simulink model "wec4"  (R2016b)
settings: Solver=ode4  StartTime=0  StopTime=1000  FixedStep=0.005  MaxStep=0.005  RelTol=1e-3  EnableMultiTasking=on
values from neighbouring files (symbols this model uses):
  arAdaptiveLawData = 1/2*zModelSimple.zModelPto.arFreq.*     zModelSimple.zModelPto.arMagnitude./     cos(zModelSimple.zModelPto.arPhase*pi/180+pi/2)    [IMPACT_Control.m]
  arAdaptiveLawDataX = 1/2*zModelSimpleX.zModelPto.arFreq.*         zModelSimpleX.zModelPto.arMagnitude./         cos(zModelSimpleX.zModelPto.arPhase*pi/180+pi/2)    [IMPACT_Control.m]
  arControllerRampGain = [0,0,1,1]    [IMPACT_Control.m]
  arControllerRampTime = [0 rStartRampTime rStartRampTime+rRampTimeLength 8000]    [IMPACT_Control.m]
  arEkfInitialisation = zeros(1,11)    [IMPACT_Control.m]
  arEkfInitialisationX = zeros(1,11)    [IMPACT_Control.m]
  arFrequency = zModelSimple.zModelPto.arFreq    [IMPACT_Control.m]
  arFrequencyRange = zModelSimple.zModelPto.arFreq    [IMPACT_Control.m]
  arFrequencyX = zModelSimpleX.zModelPto.arFreq    [IMPACT_Control.m]
  arImpedance = 1./zModelSimple.zModelPto.arMagnitude./zModelSimple.zModelPto.arFreq    [IMPACT_Control.m]
  arImpedanceX = 1./zModelSimpleX.zModelPto.arMagnitude./zModelSimpleX.zModelPto.arFreq    [IMPACT_Control.m]
  CentralPTOPreload = -1.6113e+07    (= -16113000)    [wecSimInputFile.m]
  F1 = [4.243 2.375 -12.243]    [wecSimInputFile.m]
  F2 = [4.243 -2.375 -12.243]    [wecSimInputFile.m]
  F3 = [-4.243 -2.375 -12.243]    [wecSimInputFile.m]
  F4 = [-4.243 2.375 -12.243]    [wecSimInputFile.m]
  FC = [0 0 -14]    [wecSimInputFile.m]
  iAdaptiveDamping = 0    [wec4IMPACT_Project.m]    (also in IMPACT_Control.m = handles.iAdaptiveDamping; wec1_IMPACT_Project.m; wec2_IMPACT_Project.m; wec3_IMPACT_Project.m)
  iControlType = 2    [wec4IMPACT_Project.m]    (also in IMPACT_Control.m = handles.iControlType; wec1_IMPACT_Project.m = 1; wec2_IMPACT_Project.m = 1; wec3_IMPACT_Project.m = 1)
  iPtoPositionConstraint = 1    [wec4IMPACT_Project.m]    (also in IMPACT_Control.m = handles.iPtoPositionConstraint; wec1_IMPACT_Project.m = 0; wec2_IMPACT_Project.m; wec3_IMPACT_Project.m)
  iSensorNoise = 0    [IMPACT_Control.m]
  m = m+1    (= 2)    [checkParamFile.m]
  PTOrotation = atan((T1(2)-F1(2))/(T1(1)-F1(1)))    [wecSimInputFile.m]
  rCogFloater = -8    [wec4_IMPACT_Model.m]    (also in paramInitial.m = get( handles.edit_rCogFloater, 'String' ); wec1_IMPACT_Model.m = -18; wec2_IMPACT_Model.m = -8.5; wec3_IMPACT_Model.m = -0.7)
  rCogSpar = -36.6    [wec4_IMPACT_Model.m]    (also in paramInitial.m = get( handles.edit_rCogSpar, 'String' ); wec3_IMPACT_Model.m = -21.3; wec3_IMPACT_Model2.m = -21.3)
  rDisplacementLimit = 10.000000    (= 10)    [wec4IMPACT_Project.m]    (also in IMPACT_Control.m = getValue(handles.edit_displacementLimit); wec1_IMPACT_Project.m; wec2_IMPACT_Project.m; wec3_IMPACT_Project.m = 3)
  rDisplacementLimitX = 10.000000    (= 10)    [wec4IMPACT_Project.m]    (also in IMPACT_Control.m = getValue(handles.edit_displacementLimitX); wec1_IMPACT_Project.m = 0; wec2_IMPACT_Project.m; wec3_IMPACT_Project.m = 0)
  rGainForAntiWIndUp = tfControllerDiscrete.rGain    [IMPACT_Control.m]
  rGainForAntiWIndUpX = tfControllerXDiscrete.rGain    [IMPACT_Control.m]
  rMaxForcePto = 300000000.000000    (= 300000000)    [wec4IMPACT_Project.m]    (also in IMPACT_Control.m = getValue(handles.edit_maxForcePto); wec1_IMPACT_Project.m = 1e+15; wec2_IMPACT_Project.m = 1e+15; wec3_IMPACT_Project.m = 1000000000)
  rMinForcePto = -300000000.000000    (= -300000000)    [wec4IMPACT_Project.m]    (also in IMPACT_Control.m = getValue(handles.edit_minForcePto); wec1_IMPACT_Project.m = -1e+15; wec2_IMPACT_Project.m = -1e+15; wec3_IMPACT_Project.m = -1000000000)
  rMooringX = 20000    [wec4_IMPACT_Model.m]    (also in paramInitial.m = get( handles.edit_rMooringX, 'String' ); wec3_IMPACT_Model.m = 10000; wec3_IMPACT_Model2.m = 10000)
  rMooringZ = 10000    [wec4_IMPACT_Model.m]    (also in paramInitial.m = get( handles.edit_rMooringZ, 'String' ); wec3_IMPACT_Model.m = 0; wec3_IMPACT_Model2.m = 0)
  rOutputSampleTime = 0.010000    (= 0.01)    [wec4IMPACT_Project.m]    (also in IMPACT_Control.m = getValue(handles.edit_outputSampleTime); wec1_IMPACT_Project.m; wec2_IMPACT_Project.m; wec3_IMPACT_Project.m)
  rPassiveDampingGain = -604830.000000    (= -604830)    [wec4IMPACT_Project.m]    (also in IMPACT_Control.m = getValue(handles.edit_gainPLD); wec1_IMPACT_Project.m = -214018.1537; wec2_IMPACT_Project.m = -1948070; wec3_IMPACT_Project.m = -519390)
  rPassiveDampingGainX = -278660.000000    (= -278660)    [wec4IMPACT_Project.m]    (also in IMPACT_Control.m = getValue(handles.edit_gainPLDX); wec1_IMPACT_Project.m = 0; wec2_IMPACT_Project.m = 0; wec3_IMPACT_Project.m = 0)
  rTetherPretension = 1.6113e+07    (= 16113000)    [wec4_IMPACT_Model.m]    (also in paramInitial.m = get( handles.edit_rTetherPretension, 'String' ); wec3_IMPACT_Model.m = 0; wec3_IMPACT_Model2.m = 0)
  rTetherSpring = 500000    [wec4_IMPACT_Model.m]    (also in paramInitial.m = get( handles.edit_rTetherSpring, 'String' ); wec3_IMPACT_Model.m = 0; wec3_IMPACT_Model2.m = 0)
  rUpperFrequencyLimit = EKFFloater.upperFreq    [IMPACT_Control.m]
  rXf = 4.243    [wec4AdditionalParams.m]
  rXs = 16.075    [wec4AdditionalParams.m]
  rYf = 2.375    [wec4AdditionalParams.m]
  rYs = 16.075    [wec4AdditionalParams.m]
  rZf = 4.243    [wec4AdditionalParams.m]
  rZs = 2.4350    (= 2.435)    [wec4AdditionalParams.m]
  rZTetherF = 6    [wec4AdditionalParams.m]
  rZTetherS = 2.4350    (= 2.435)    [wec4AdditionalParams.m]
  s = tf('s')    [wec4_IMPACT_Model.m]    (also in IMPACT_Control.m; wec1_IMPACT_Model.m; wec2_IMPACT_Model.m; wec3_IMPACT_Model.m)
  SidePTO1Preload = PreloadPTOCorner    (= 0)    [wecSimInputFile.m]
  SidePTO2Preload = PreloadPTOCorner    (= 0)    [wecSimInputFile.m]
  SidePTO3Preload = PreloadPTOCorner    (= 0)    [wecSimInputFile.m]
  SidePTO4Preload = PreloadPTOCorner    (= 0)    [wecSimInputFile.m]
  simu = simulationClass()    [wecSimInputFile.m]
  T1 = [16.075 16.075 -34.165]    [wecSimInputFile.m]
  T2 = [16.075 -16.075 -34.165]    [wecSimInputFile.m]
  T3 = [-16.075 -16.075 -34.165]    [wecSimInputFile.m]
  T4 = [-16.075 16.075 -34.165]    [wecSimInputFile.m]
  TC = [0 0 -34.165]    [wecSimInputFile.m]
  waves = waveClass('irregular')    [wecSimInputFile.m]
  Z = magPhaseToComplex(zModelTf)    [IMPACT_Control.m]
undefined symbols (not defined in the file or in its folder): arControllerDiscreteDen, arControllerDiscreteNum, arControllerDiscreteXDen, arControllerDiscreteXNum, arExcForceFloaterDen, arExcForceFloaterNum, arExcForceFloaterXDen, arExcForceFloaterXNum, arExcForceSparDen, arExcForceSparNum, arExcForceSparXDen, arExcForceSparXNum, arFexcFloaterDen, arFexcFloaterNum, arFexcFloaterXDen, arFexcFloaterXNum, arFexcSparDen, arFexcSparNum, arFexcSparXDen, arFexcSparXNum, Body, body, constraint, CTTime, deg, Elements, geometry, IRKB, kg, lenJ, mooring, N, pto, rAccelerationGainFloater, rAccelerationGainFloaterX, rAccelerationGainSpar, rAccelerationGainSparX, rad, rBuoyancyGainFloater, rBuoyancyGainFloaterX, rBuoyancyGainSpar, rBuoyancyGainSparX, rDampingGainFloater, rDampingGainFloaterX, rDampingGainSpar, rDampingGainSparX, Rigid, rMaxFocePto, wec4_float, wec4_reactor, WECSim_Lib, X, Y
libraries: nesl_utility x380, sm_lib x170, vrlib x91, simulink x12, WECSim_Lib x4
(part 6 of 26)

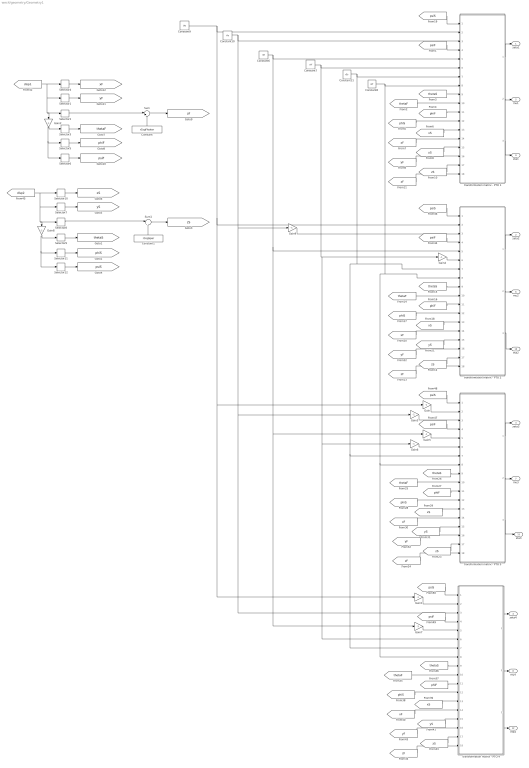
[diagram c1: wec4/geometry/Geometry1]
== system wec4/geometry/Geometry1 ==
  Constant : Constant  Value=rCogFloater
  Constant1 : Constant  Value=rCogSpar
  Constant10 : Constant  Value=rYs
  Constant11 : Constant  Value=rZs
  Constant6 : Constant  Value=rXf
  Constant7 : Constant  Value=rYf
  Constant8 : Constant  Value=rZf
  Constant9 : Constant  Value=rXs
  Gain{,1..9} (10 alike) : Gain  Gain=-1
  Selector1 : Selector  InputPortWidth=6  IndexOptions=Index vector (dialog)  Indices=2  OutputSizes=1
  Selector10 : Selector  InputPortWidth=6  IndexOptions=Index vector (dialog)  Indices=1  OutputSizes=1
  Selector11 : Selector  InputPortWidth=6  IndexOptions=Index vector (dialog)  Indices=5  OutputSizes=1
  Selector12 : Selector  InputPortWidth=6  IndexOptions=Index vector (dialog)  Indices=6  OutputSizes=1
  Selector2 : Selector  InputPortWidth=6  IndexOptions=Index vector (dialog)  Indices=3  OutputSizes=1
  Selector3 : Selector  InputPortWidth=6  IndexOptions=Index vector (dialog)  Indices=4  OutputSizes=1
  Selector4 : Selector  InputPortWidth=6  IndexOptions=Index vector (dialog)  Indices=1  OutputSizes=1
  Selector5 : Selector  InputPortWidth=6  IndexOptions=Index vector (dialog)  Indices=5  OutputSizes=1
  Selector6 : Selector  InputPortWidth=6  IndexOptions=Index vector (dialog)  Indices=6  OutputSizes=1
  Selector7 : Selector  InputPortWidth=6  IndexOptions=Index vector (dialog)  Indices=2  OutputSizes=1
  Selector8 : Selector  InputPortWidth=6  IndexOptions=Index vector (dialog)  Indices=3  OutputSizes=1
  Selector9 : Selector  InputPortWidth=6  IndexOptions=Index vector (dialog)  Indices=4  OutputSizes=1
  Sum : Sum  Inputs=|+-
  Sum1 : Sum  Inputs=|+-
  transformation matrix - PTO 1 : Subsystem
  transformation matrix - PTO 2 : Subsystem
  transformation matrix - PTO 3 : Subsystem
  transformation matrix - PTO 4 : Subsystem
  zeta1 : Outport
  zeta2 : Outport  Port=2
  zeta3 : Outport  Port=3
  zeta4 : Outport  Port=4
  mu1 : Outport  Port=5
  mu2 : Outport  Port=6
  mu3 : Outport  Port=7
  mu4 : Outport  Port=8
  eta1 : Outport  Port=9
  eta2 : Outport  Port=10
  eta3 : Outport  Port=11
  eta4 : Outport  Port=12
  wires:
  [phiS] -> transformation matrix - PTO 3/12(PhiS)
  [xF] -> transformation matrix - PTO 1/14(x_f)
  [thetaS] -> transformation matrix - PTO 4/9(thetaS)
  [yS] -> transformation matrix - PTO 4/15(y_s)
  [phiS] -> transformation matrix - PTO 4/12(PhiS)
  [zS] -> transformation matrix - PTO 4/17(z_s)
  [phiF] -> transformation matrix - PTO 4/11(PhiF)
  [thetaF] -> transformation matrix - PTO 4/10(thetaF)
  [yF] -> transformation matrix - PTO 4/16(y_f)
  [psiF] -> transformation matrix - PTO 1/4(PsiF)
  [thetaF] -> transformation matrix - PTO 3/10(thetaF)
  [phiS] -> transformation matrix - PTO 1/12(PhiS)
  [psiF] -> transformation matrix - PTO 3/4(PsiF)
  [thetaF] -> transformation matrix - PTO 1/10(thetaF)
  [disp1] -> Gain2/1, Selector2/1, Selector1/1, Selector4/1
  Selector1/1 -> [yF]
  Selector3/1 -> [thetaF]
  [xS] -> transformation matrix - PTO 1/13(x_s)
  [zS] -> transformation matrix - PTO 3/17(z_s)
  [zS] -> transformation matrix - PTO 2/17(z_s)
  [phiF] -> transformation matrix - PTO 2/11(PhiF)
  [psiS] -> transformation matrix - PTO 3/1(PsiS)
  [psiF] -> transformation matrix - PTO 4/4(PsiF)
  [xS] -> transformation matrix - PTO 2/13(x_s)
  [psiS] -> transformation matrix - PTO 4/1(PsiS)
  Selector10/1 -> [xS]
  Gain1/1 -> transformation matrix - PTO 4/2(rXs)
  Constant6/1 -> transformation matrix - PTO 2/5(rXf), Gain5/1, Gain7/1, transformation matrix - PTO 1/5(rXf)
  Selector5/1 -> [phiF]
  Selector12/1 -> [psiS]
  Gain6/1 -> transformation matrix - PTO 3/6(rYf)
  Gain3/1 -> transformation matrix - PTO 3/3(rYs)
  Gain7/1 -> transformation matrix - PTO 4/5(rXf)
  Constant10/1 -> Gain9/1, transformation matrix - PTO 4/3(rYs), Gain3/1, transformation matrix - PTO 1/3(rYs)
  Gain/1 -> transformation matrix - PTO 3/2(rXs)
  Gain9/1 -> transformation matrix - PTO 2/3(rYs)
  Constant9/1 -> transformation matrix - PTO 2/2(rXs), Gain/1, Gain1/1, transformation matrix - PTO 1/2(rXs)
  Gain4/1 -> transformation matrix - PTO 2/6(rYf)
  Gain5/1 -> transformation matrix - PTO 3/5(rXf)
  Constant11/1 -> transformation matrix - PTO 3/7(rZs), transformation matrix - PTO 4/7(rZs), transformation matrix - PTO 2/7(rZs), transformation matrix - PTO 1/7(rZs)
  Constant8/1 -> transformation matrix - PTO 2/8(rZf), transformation matrix - PTO 3/8(rZf), transformation matrix - PTO 4/8(rZf), transformation matrix - PTO 1/8(rZf)
  Constant7/1 -> transformation matrix - PTO 4/6(rYf), Gain6/1, Gain4/1, transformation matrix - PTO 1/6(rYf)
  [thetaS] -> transformation matrix - PTO 2/9(thetaS)
  [xF] -> transformation matrix - PTO 2/14(x_f)
  [zF] -> transformation matrix - PTO 2/18(z_f)
  [thetaS] -> transformation matrix - PTO 3/9(thetaS)
  [zF] -> transformation matrix - PTO 4/18(z_f)
  [phiF] -> transformation matrix - PTO 3/11(PhiF)
  [thetaF] -> transformation matrix - PTO 2/10(thetaF)
  [phiS] -> transformation matrix - PTO 2/12(PhiS)
  [zS] -> transformation matrix - PTO 1/17(z_s)
  [yS] -> transformation matrix - PTO 1/15(y_s)
  [yF] -> transformation matrix - PTO 1/16(y_f)
  [zF] -> transformation matrix - PTO 1/18(z_f)
  Selector7/1 -> [yS]
  [thetaS] -> transformation matrix - PTO 1/9(thetaS)
  Selector11/1 -> [phiS]
  [disp2] -> Selector10/1, Selector7/1, Selector8/1, Gain8/1
  [zF] -> transformation matrix - PTO 3/18(z_f)
  Selector4/1 -> [xF]
  Selector2/1 -> Sum/1
  Selector9/1 -> [thetaS]
  [psiS] -> transformation matrix - PTO 1/1(PsiS)
  Selector6/1 -> [psiF]
  [psiS] -> transformation matrix - PTO 2/1(PsiS)
  [psiF] -> transformation matrix - PTO 2/4(PsiF)
  [phiF] -> transformation matrix - PTO 1/11(PhiF)
  transformation matrix - PTO 4/2(mu) -> mu4/1
  transformation matrix - PTO 3/2(mu) -> mu3/1
  transformation matrix - PTO 2/1(zeta) -> zeta2/1
  transformation matrix - PTO 4/3(eta) -> eta4/1
  transformation matrix - PTO 3/1(zeta) -> zeta3/1
  transformation matrix - PTO 1/3(eta) -> eta1/1
  transformation matrix - PTO 3/3(eta) -> eta3/1
  transformation matrix - PTO 1/2(mu) -> mu1/1
  transformation matrix - PTO 2/2(mu) -> mu2/1
  transformation matrix - PTO 4/1(zeta) -> zeta4/1
  transformation matrix - PTO 2/3(eta) -> eta2/1
  transformation matrix - PTO 1/1(zeta) -> zeta1/1
  Constant/1 -> Sum/2
  Sum/1 -> [zF]
  Selector8/1 -> Sum1/1
  Constant1/1 -> Sum1/2
  Sum1/1 -> [zS]
  Gain2/1 -> Selector6/1, Selector5/1, Selector3/1
  Gain8/1 -> Selector11/1, Selector12/1, Selector9/1
  [yS] -> transformation matrix - PTO 2/15(y_s)
  [yF] -> transformation matrix - PTO 2/16(y_f)
  [xF] -> transformation matrix - PTO 3/14(x_f)
  [xS] -> transformation matrix - PTO 3/13(x_s)
  [yF] -> transformation matrix - PTO 3/16(y_f)
  [yS] -> transformation matrix - PTO 3/15(y_s)
  [xF] -> transformation matrix - PTO 4/14(x_f)
  [xS] -> transformation matrix - PTO 4/13(x_s)

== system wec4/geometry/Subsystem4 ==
  Zetas : Inport
  mus : Inport  Port=2
  etas : Inport  Port=3
  Constant : Constant  Value="sqrt( (F1(1)-T1(1))^2 + (F1(2)-T1(2))^2 + (F1(3)-T1(3))^2  )"
  Constant1 : Constant  Value="sqrt( (F2(1)-T2(1))^2 + (F2(2)-T2(2))^2 + (F2(3)-T2(3))^2  )"
  Constant2 : Constant  Value="sqrt( (F3(1)-T3(1))^2 + (F3(2)-T3(2))^2 + (F3(3)-T3(3))^2  )"
  Constant3 : Constant  Value="sqrt( (F4(1)-T4(1))^2 + (F4(2)-T4(2))^2 + (F4(3)-T4(3))^2  )"
  Divide2 : Product  Inputs=*/
  Mux : Mux
  Saturation : Saturate  UpperLimit=1  LowerLimit=-1
  Sum{1..3,28} (4 alike) : Sum  Inputs=++|
  Trigonometric Function : Trigonometry  Operator=atan2
  Trigonometric Function1 : Trigonometry  Operator=atan2
  Trigonometric Function2 : Trigonometry  Operator=asin
  Trigonometric Function3 : Trigonometry  Operator=atan2
  gammas : Outport
  betas : Outport  Port=2
  deltas : Outport  Port=3
  alphas : Outport  Port=4
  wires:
  Constant/1 -> Sum28/1
  [ptoDis1] -> Sum28/2
  Sum28/1 -> Mux/1
  Constant1/1 -> Sum1/1
  [ptoDis2] -> Sum1/2
  Sum1/1 -> Mux/2
  Constant2/1 -> Sum2/1
  [ptoDis3] -> Sum2/2
  Sum2/1 -> Mux/3
  Constant3/1 -> Sum3/1
  [ptoDis4] -> Sum3/2
  Sum3/1 -> Mux/4
  Mux/1 -> Divide2/2
  Zetas/1 -> Trigonometric Function3/2, Trigonometric Function/2
  Trigonometric Function/1 -> betas/1
  mus/1 -> Trigonometric Function3/1, Trigonometric Function1/2
  Trigonometric Function1/1 -> deltas/1
  etas/1 -> Divide2/1, Trigonometric Function/1, Trigonometric Function1/1
  Divide2/1 -> Saturation/1
  Trigonometric Function3/1 -> alphas/1
  Trigonometric Function2/1 -> gammas/1
  Saturation/1 -> Trigonometric Function2/1

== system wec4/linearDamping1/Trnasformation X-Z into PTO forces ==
  Force X : Inport
  Force Z : Inport  Port=2
  Constant{,1..3} (4 alike) : Constant  Value=2
  Divide : Product  Inputs=/*
  Divide1 : Product  Inputs=/*
  Product{1..2,4..5,8..10,22} (8 alike) : Product
  Product{6..7,23..24} (4 alike) : Product  Inputs=3
  Sum10 : Sum  Inputs=|++
  Sum2 : Sum  Inputs=|+-
  Sum3 : Sum  Inputs=|++
  Sum4 : Sum  Inputs=|++
  Trigonometric Function{,1,8..9} (4 alike) : Trigonometry  Operator=cos
  Trigonometric Function{2..3,10..11} (4 alike) : Trigonometry
  Force PTOs 3-4 : Outport
  Force PTOs 1-2 : Outport  Port=2
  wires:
  [beta1] -> Trigonometric Function/1
  [beta3] -> Trigonometric Function1/1
  Divide/1 -> Force PTOs 1-2/1  "F1"
  Sum3/1 -> Divide/1
  Sum2/1 -> Divide/2
  Product7/1 -> Sum3/2
  Product6/1 -> Sum3/1
  Product4/1 -> Sum2/2
  Product5/1 -> Sum2/1
  Constant1/1 -> Product7/3
  Constant/1 -> Product6/3
  Trigonometric Function3/1 -> Product7/1  "sinLambda1"
  Trigonometric Function2/1 -> Product4/1, Product6/2  "sinLambda3"
  Product2/1 -> Product7/2, Product5/1  "cosLambda3"
  Trigonometric Function1/1 -> Product2/2
  [gamma3] -> Trigonometric Function2/1
  Product1/1 -> Product6/1  "cosLambda1"
  Trigonometric Function/1 -> Product1/2
  [gamma1] -> Trigonometric Function3/1
  Force Z/1 -> Product5/2, Product22/2
  Force X/1 -> Product4/2, Product10/2
  [beta3] -> Trigonometric Function8/1
  [beta1] -> Trigonometric Function9/1
  Sum10/1 -> Divide1/1
  Sum4/1 -> Divide1/2
  Product24/1 -> Sum10/2
  Product23/1 -> Sum10/1
  Product10/1 -> Sum4/2
  Product22/1 -> Sum4/1
  Constant3/1 -> Product24/3
  Constant2/1 -> Product23/3
  Trigonometric Function11/1 -> Product24/1  "sinLambda3"
  Trigonometric Function10/1 -> Product23/2, Product10/1  "sinLambda1"
  Product9/1 -> Product22/1, Product24/2  "cosLambda1"
  Trigonometric Function9/1 -> Product9/2
  [gamma1] -> Trigonometric Function10/1
  [cosAlpha3] -> Product8/1, Product2/1
  Product8/1 -> Product23/1  "cosLambda3"
  Trigonometric Function8/1 -> Product8/2
  [gamma3] -> Trigonometric Function11/1
  [cosAlpha1] -> Product9/1, Product1/1
  Divide1/1 -> Force PTOs 3-4/1  "F3"

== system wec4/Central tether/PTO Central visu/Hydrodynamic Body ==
  Additional Linear Damping Force Calculation : Subsystem
  B2B Subsystem : Subsystem  Variant=on
  Bus Creator : BusCreator  Inputs=6
  Bus Creator1 : BusCreator  Inputs=3
  Bus Selector1 : BusSelector  OutputSignals=F_Excitation,F_RadiationDamping,F_AddedMass,F_Restoring,F_MorrisonAndViscous,F_LinearDamping
  Bus Selector2 : BusSelector  OutputSignals=disp,vel,acc
  Hydrostatic Restoring Force Calculation : Subsystem
  Morrison Element and ViscousDampingForceCalculation : Subsystem
  Nonlinear Wave Elevation : Subsystem  TreatAsAtomicUnit=on  SystemSampleTime=simu.dtNL
  Structure : Subsystem
  Sum : Sum  Inputs=+-----
  To Workspace : ToWorkspace  VariableName=body3_out  SaveFormat=Structure With Time  SampleTime=-1
  Wave Diffraction and Excitation Force Calculation : Subsystem
  Wave Radiation Forces Calculation : Subsystem
  Conn : PMIOPort  Port=1  Side=Right
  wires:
  Additional Linear Damping Force Calculation/1(F_LinearDamping) -> Bus Creator/6
  Bus Creator/1 -> Bus Selector1/1, Bus Creator1/3  "BUS(7): Forces"
  Bus Selector2/1 -> [disp3]  "<disp>"
  Bus Selector2/3 -> [acc3]  "<acc>"
  Bus Selector2/2 -> [vel3]  "<vel>"
  Structure/1(Response) -> Bus Creator1/1, Bus Selector2/1
  Sum/1 -> Bus Creator1/2, Structure/1(Total Force)  "F_Total"
  Bus Creator1/1 -> To Workspace/1
  Bus Selector1/4 -> Sum/4  "<F_Restoring>"
  Bus Selector1/3 -> Sum/3  "<F_AddedMass>"
  Bus Selector1/5 -> Sum/5  "<F_MorrisonAndViscous>"
  Bus Selector1/2 -> Sum/2  "<F_RadiationDamping>"
  Bus Selector1/1 -> Sum/1  "<F_Excitation>"
  Bus Selector1/6 -> Sum/6  "<F_LinearDamping>"
  [acc3] -> B2B Subsystem/2(acc_in), Morrison Element and ViscousDampingForceCalculation/2(Acceleration)
  [vel3] -> Morrison Element and ViscousDampingForceCalculation/3(Velocity), Additional Linear Damping Force Calculation/1(Velocity), B2B Subsystem/1(vel_in)
  B2B Subsystem/2(acc) -> Wave Radiation Forces Calculation/2(Acceleration)
  B2B Subsystem/1(vel) -> Wave Radiation Forces Calculation/1(Velocity)
  [disp3] -> Hydrostatic Restoring Force Calculation/1(Displacement), Morrison Element and ViscousDampingForceCalculation/1(Displacement), Nonlinear Wave Elevation/1(Displacement), Wave Diffraction and Excitation Force Calculation/2(Displacement)
  Nonlinear Wave Elevation/1(Wave Elevation) -> Wave Diffraction and Excitation Force Calculation/3(WaveElv), Hydrostatic Restoring Force Calculation/2(Wave Elv)
  Hydrostatic Restoring Force Calculation/1(F_Restoring) -> Bus Creator/4
  Wave Radiation Forces Calculation/1(F_RadiationDamping) -> Bus Creator/2
  Wave Diffraction and Excitation Force Calculation/1(F_Excitation) -> Bus Creator/1
  Wave Radiation Forces Calculation/2(F_AddedMass) -> Bus Creator/3
  [Clock] -> Nonlinear Wave Elevation/2(Time), Wave Diffraction and Excitation Force Calculation/1(Time), Morrison Element and ViscousDampingForceCalculation/4(Time), Wave Radiation Forces Calculation/3(Time)
  Morrison Element and ViscousDampingForceCalculation/1(F_MorrisonAndViscous) -> Bus Creator/5
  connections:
  Conn/RConn1 -- Structure/RConn1

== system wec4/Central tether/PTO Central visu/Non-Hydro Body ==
  Bus Creator : BusCreator  Inputs=6
  Bus Creator1 : BusCreator  Inputs=3
  Bus Selector1 : BusSelector  OutputSignals=F_Excitation,F_RadiationDamping,F_AddedMass,F_Restoring,F_MorrisonAndViscous,F_LinearDamping
  Constant{,1..3,5} (5 alike) : Constant  Value=[0 0 0 0 0 0]
  Structure : Subsystem
  Sum : Sum  Inputs=+-----
  To Workspace : ToWorkspace  VariableName=body3_out  SaveFormat=Structure With Time  SampleTime=-1
  Weight and Buoyancy : Subsystem
  Conn : PMIOPort  Port=1  Side=Right
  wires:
  Bus Creator/1 -> Bus Creator1/3, Bus Selector1/1  "BUS(7): Forces"
  Structure/1(Response) -> Bus Creator1/1
  Sum/1 -> Bus Creator1/2, Structure/1(Total Force)  "F_Total"
  Bus Creator1/1 -> To Workspace/1
  Bus Selector1/4 -> Sum/4  "<F_Restoring>"
  Bus Selector1/3 -> Sum/3  "<F_AddedMass>"
  Bus Selector1/5 -> Sum/5  "<F_MorrisonAndViscous>"
  Bus Selector1/2 -> Sum/2  "<F_RadiationDamping>"
  Bus Selector1/1 -> Sum/1  "<F_Excitation>"
  Bus Selector1/6 -> Sum/6  "<F_LinearDamping>"
  Constant5/1 -> Bus Creator/6  "F_LinearDamping"
  Constant3/1 -> Bus Creator/5  "F_MorrisonAndViscous"
  Constant2/1 -> Bus Creator/3  "F_AddedMass"
  Constant1/1 -> Bus Creator/2  "F_RadiationDamping"
  Constant/1 -> Bus Creator/1  "F_Excitation"
  Weight and Buoyancy/1(Out1) -> Bus Creator/4  "F_Restoring"
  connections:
  Conn/RConn1 -- Structure/RConn1

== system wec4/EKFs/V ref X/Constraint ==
  1/2B : Inport
  Amp : Inport  Port=2
  ekfFrequency : Inport  Port=3
  Constant1 : Constant  Value=rDisplacementLimitX
  Constant3 : Constant  Value=iPtoPositionConstraint
  Divide3 : Product  Inputs=**/
  MinMax : MinMax  Inputs=2
  MinMax1 : MinMax  Function=max  Inputs=2
  Mux : Mux  Inputs=3
  Scope : Scope
  Switch2 : Switch  Criteria=u2 > Threshold
  To avoid dividing by 0 : Constant  Value=100
  referenceVelocity : Outport
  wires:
  1/2B/1 -> Mux/2, Switch2/3, MinMax/2
  Mux/1 -> Scope/1
  Switch2/1 -> referenceVelocity/1, Mux/3
  Constant3/1 -> Switch2/2
  Amp/1 -> MinMax1/1
  To avoid dividing by 0/1 -> MinMax1/2
  Divide3/1 -> MinMax/1
  MinMax1/1 -> Divide3/3
  Constant1/1 -> Divide3/1
  ekfFrequency/1 -> Divide3/2
  MinMax/1 -> Switch2/1, Mux/1

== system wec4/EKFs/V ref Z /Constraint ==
  1/2B : Inport
  Amp : Inport  Port=2
  ekfFrequency : Inport  Port=3
  Constant1 : Constant  Value=rDisplacementLimit
  Constant3 : Constant  Value=iPtoPositionConstraint
  Divide3 : Product  Inputs=**/
  MinMax : MinMax  Inputs=2
  MinMax1 : MinMax  Function=max  Inputs=2
  Mux : Mux  Inputs=3
  Scope : Scope
  Switch2 : Switch  Criteria=u2 > Threshold
  To avoid dividing by 0 : Constant  Value=100
  referenceVelocity : Outport
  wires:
  MinMax/1 -> Mux/1, Switch2/1
  ekfFrequency/1 -> Divide3/2
  MinMax1/1 -> Divide3/3
  Divide3/1 -> MinMax/1
  To avoid dividing by 0/1 -> MinMax1/2
  Amp/1 -> MinMax1/1
  Constant3/1 -> Switch2/2
  Switch2/1 -> Mux/3, referenceVelocity/1
  Mux/1 -> Scope/1
  1/2B/1 -> MinMax/2, Switch2/3, Mux/2
  Constant1/1 -> Divide3/1

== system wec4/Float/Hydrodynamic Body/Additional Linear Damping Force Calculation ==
  Velocity : Inport
  Additional Linear Damping Matrix (diagonal) : Constant  Value=body.hydroForce.linearDamping
  Product1 : Product  Multiplication=Matrix(*)
  F_LinearDamping : Outport
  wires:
  Velocity/1 -> Product1/2  "v"
  Product1/1 -> F_LinearDamping/1  "F_LinearDamping"
  Additional Linear Damping Matrix (diagonal)/1 -> Product1/1  "C"

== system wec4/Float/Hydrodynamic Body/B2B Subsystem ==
  note: 1) Add Subsystem or Model blocks as valid variant choices. 2) You cannot connect blocks at this level. At simulation, connectivity is automatically determined, based on the active variant and port name matching.
  vel_in : Inport
  acc_in : Inport  Port=2
  B2B : Subsystem  VariantControl=sv_B2B
  noB2B : Subsystem  VariantControl=sv_noB2B
  vel : Outport
  acc : Outport  Port=2

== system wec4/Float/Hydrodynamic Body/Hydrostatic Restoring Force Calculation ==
  Displacement : Inport
  Wave Elv : Inport  Port=2
  Add : Sum  Inputs=+-
  Center of Gravity : Constant  Value=body.cg
  Constant : Constant  Value=[0 0 0]
  Linear and Nonlinear Restoring Force Variant Subsystem : Subsystem  Variant=on
  Mux : Mux  Inputs=2
  F_Restoring : Outport
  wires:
  Add/1 -> Linear and Nonlinear Restoring Force Variant Subsystem/1(In1)  "x_cg"
  Wave Elv/1 -> Linear and Nonlinear Restoring Force Variant Subsystem/2(In2)
  Constant/1 -> Mux/2
  Center of Gravity/1 -> Mux/1  "cg"
  Mux/1 -> Add/2
  Linear and Nonlinear Restoring Force Variant Subsystem/1(Out1) -> F_Restoring/1  "F_Restoring"
  Displacement/1 -> Add/1  "x"

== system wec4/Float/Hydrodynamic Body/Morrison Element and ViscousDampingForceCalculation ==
  Displacement : Inport
  Acceleration : Inport  Port=2
  Velocity : Inport  Port=3
  Time : Inport  Port=4
  Abs1 : Abs
  Morrison Element Variant Subsystem : Subsystem  Variant=on
  Product : Product
  Product1 : Product  Multiplication=Matrix(*)
  Transport Delay : TransportDelay  DelayTime=10e-8
  "VisSum " : Sum  Inputs=+-
  "Viscous Damping Matrix (diagonal) " : Constant  Value=body.hydroForce.visDrag
  F_MorrisonAndViscous : Outport
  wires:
  Time/1 -> Morrison Element Variant Subsystem/4(time)
  Morrison Element Variant Subsystem/1(morison_force) -> "VisSum "/2
  Displacement/1 -> Morrison Element Variant Subsystem/1(displacement)
  Product/1 -> Product1/2  "v * |v|"
  "Viscous Damping Matrix (diagonal) "/1 -> Product1/1  "0.5 * cd * rho *A"
  Product1/1 -> "VisSum "/1
  Abs1/1 -> Product/2
  Acceleration/1 -> Transport Delay/1
  Transport Delay/1 -> Morrison Element Variant Subsystem/3(acceleration)
  "VisSum "/1 -> F_MorrisonAndViscous/1  "F_MorrisonAndViscous"
  Velocity/1 -> Abs1/1, Product/1, Morrison Element Variant Subsystem/2(velocity)

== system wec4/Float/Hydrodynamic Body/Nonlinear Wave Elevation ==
  Displacement : Inport
  Time : Inport  Port=2
  Add : Sum  Inputs=+-
  Center of Gravity : Constant  Value=body.cg
  Constant : Constant  Value=[0 0 0]
  Linear or Instantaneous Free Surface : Subsystem  Variant=on
  Mux : Mux  Inputs=2
  Wave Elevation : Outport
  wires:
  Time/1 -> Linear or Instantaneous Free Surface/2(In2)
  Constant/1 -> Mux/2
  Center of Gravity/1 -> Mux/1  "cg"
  Mux/1 -> Add/2
  Add/1 -> Linear or Instantaneous Free Surface/1(In1)  "x_cg"
  Linear or Instantaneous Free Surface/1(Out1) -> Wave Elevation/1
  Displacement/1 -> Add/1  "x"

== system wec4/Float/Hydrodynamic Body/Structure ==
  Total Force : Inport
  Body Properties : sm_lib/Body Elements/Solid  InertiaType=Custom  Mass=body.mass  MassUnits=kg  CenterOfMass=[0 0 0]  CenterOfMassUnits=m  MomentsOfInertia=body.momOfInertia  MomentsOfInertiaUnits=kg*m^2  ProductsOfInertia=[0 0 0]  ProductsOfInertiaUnits=kg*m^2  DensityBased=on  Density=1000  DensityUnits=kg/(m^3)  DoExposeReferenceFrame=on  SerializedFrames=<Frames/>  GraphicType=FromGeometry  MarkerShape=Sphere  MarkerSize=10  MarkerSizeUnits=m  GraphicVisPropType=SimpleVisualProperties  GraphicDiffuseColor=body.viz.color  GraphicSpecularColor=[0.5 0.5 0.5 1.0]  GraphicAmbientColor=[0.15 0.15 0.15 1.0]  GraphicEmissiveColor=[0.0 0.0 0.0 1.0]  GraphicShininess=75  GraphicOpacity=body.viz.opacity  GeometryShape=FromFile  RectangleSize=[1 1]  RectangleSizeUnits=m  BrickDimensions=[1 1 1]  BrickDimensionUnits=m  CylinderRadius=1  CylinderRadiusUnits=m  CylinderLength=1  CylinderLengthUnits=m  SphereRadius=1  SphereRadiusUnits=m  EllipsoidRadii=[1 1 1]  EllipsoidRadiiUnits=m  ExtrusionCrossSection=[1 1; -1 1; -1 -1; 1 -1]  ExtrusionCrossSectionUnits=m  ExtrusionLength=1  ExtrusionLengthUnits=m  PolygonNumSides=3  PolygonOuterRadius=1  PolygonOuterRadiusUnits=m  ExtGeomFileType=STL  ExtGeomFileName=.\geometry\wec4_float.stl  ExtGeomFileUnits=m  RevolutionCrossSection=[1 1; 1 -1; 2 -1; 2 1]  RevolutionCrossSectionUnits=m  RevolutionExtent=Full  RevolutionAngle=180  RevolutionAngleUnits=deg
  External Force and Torque : sm_lib/Forces and Torques/External Force and Torque  ForceResolutionFrame=World  EnableForceX=off  EnableForceY=off  EnableForceZ=off  EnableForce=on  TorqueResolutionFrame=World  EnableTorqueX=off  EnableTorqueY=off  EnableTorqueZ=off  EnableTorque=on
  Motion Sensor : Subsystem
  Rigid Transform (Setup CG) : sm_lib/Frames and Transforms/Rigid Transform  TranslationMethod=Cartesian  TranslationStandardOffset=0  TranslationLengthUnit=m  TranslationStandardAxis=+Z  TranslationCartesianOffset=body.cg  TranslationROffset=0  TranslationROffsetUnits=m  TranslationZOffset=0  TranslationZOffsetUnits=m  TranslationThetaOffset=0  TranslationThetaOffsetUnits=deg  RotationMethod=None  RotationAngleUnits=rad  RotationStandardAxis=+Y  RotationAngle=0.05  RotationArbitraryAxis=[0.57735026918962584 0.57735026918962584 0.57735026918962584]  FollAlignAxisA=+X  BaseAlignAxisA=+Y  FollAlignAxisB=+Y  BaseAlignAxisB=+Z  RotationSequenceAxes=FollowerAxes  RotationSequence=XYX  RotationSequenceAngles=[0 0 0]  RotationSequenceAnglesUnits=deg  RotationMatrix=[1 0 0; 0 1 0; 0 0 1]
  Rigid Transform (Setup Initial Disp) : sm_lib/Frames and Transforms/Rigid Transform  TranslationMethod=Cartesian  TranslationStandardOffset=0  TranslationLengthUnit=m  TranslationStandardAxis=+Z  TranslationCartesianOffset=body.initDisp.initLinDisp  TranslationROffset=0  TranslationROffsetUnits=m  TranslationZOffset=0  TranslationZOffsetUnits=m  TranslationThetaOffset=0  TranslationThetaOffsetUnits=deg  RotationMethod=ArbitraryAxis  RotationAngleUnits=rad  RotationStandardAxis=+Y  RotationAngle=body.initDisp.initAngularDispAngle  RotationArbitraryAxis=body.initDisp.initAngularDispAxis  FollAlignAxisA=+X  BaseAlignAxisA=+Y  FollAlignAxisB=+Y  BaseAlignAxisB=+Z  RotationSequenceAxes=FollowerAxes  RotationSequence=XYX  RotationSequenceAngles=[0 0 0]  RotationSequenceAnglesUnits=deg  RotationMatrix=[1 0 0; 0 1 0; 0 0 1]
  Selector : Selector  InputPortWidth=6  IndexOptions=Index vector (dialog)  Indices=[1:3]  OutputSizes=1
  Selector1 : Selector  InputPortWidth=6  IndexOptions=Index vector (dialog)  Indices=[4:6]  OutputSizes=1
  Simulink-PS Converter1 : nesl_utility/Simulink-PS Converter  PhysicalDomain=network_engine_domain  SubClassName=ps_input  LeftPortType=input  RightPortType=output  PseudoPeriodic=off  Frequencies=[]  NoiseDistribution=none  NoiseParameters=[]  Unit=1  AffineConversion=off  InputFiltering=off  SimscapeFilterOrder=1  InputFilterTimeConstant=0.001  UdotUserProvided=1
  Simulink-PS Converter2 : nesl_utility/Simulink-PS Converter  PhysicalDomain=network_engine_domain  SubClassName=ps_input  LeftPortType=input  RightPortType=output  PseudoPeriodic=off  Frequencies=[]  NoiseDistribution=none  NoiseParameters=[]  Unit=1  AffineConversion=off  InputFiltering=off  SimscapeFilterOrder=1  InputFilterTimeConstant=0.001  UdotUserProvided=1
  World Frame : sm_lib/Frames and Transforms/World Frame
  Conn Free Surface : PMIOPort  Port=1  Side=Right
  Response : Outport
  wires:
  Total Force/1 -> Selector1/1, Selector/1
  Selector/1 -> Simulink-PS Converter1/1
  Selector1/1 -> Simulink-PS Converter2/1
  Motion Sensor/1(Response) -> Response/1
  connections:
  External Force and Torque/LConn1 -- Simulink-PS Converter1/RConn1
  External Force and Torque/LConn2 -- Simulink-PS Converter2/RConn1
  Rigid Transform (Setup Initial Disp)/RConn1 -- Body Properties/RConn1 -- External Force and Torque/RConn1 -- Motion Sensor/RConn1
  Conn Free Surface/RConn1 -- Rigid Transform (Setup CG)/LConn1
  Rigid Transform (Setup Initial Disp)/LConn1 -- Rigid Transform (Setup CG)/RConn1
  World Frame/RConn1 -- Motion Sensor/LConn1

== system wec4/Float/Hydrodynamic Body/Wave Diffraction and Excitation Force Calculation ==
  Time : Inport
  Displacement : Inport  Port=2
  WaveElv : Inport  Port=3
  Add : Sum
  If2 : If  NumInputs=2  IfExpression=u1 < u2
  Linear Wave Excitation Force Variant Subsystem : Subsystem  Variant=on
  Merge1 : Merge
  No Ramp Function : Subsystem  TreatAsAtomicUnit=on
  Nonlinear FK Force Variant Subsystem : Subsystem  Variant=on
  Product : Product
  Ramp Function : Subsystem  TreatAsAtomicUnit=on
  Ramp Function Time : Constant  Value=simu.rampTime
  F_Excitation : Outport  PortDimensions=6
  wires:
  Nonlinear FK Force Variant Subsystem/1(Out1) -> Add/2
  Linear Wave Excitation Force Variant Subsystem/1(Out1) -> Add/1
  WaveElv/1 -> Nonlinear FK Force Variant Subsystem/3(In3)
  Displacement/1 -> Nonlinear FK Force Variant Subsystem/2(In2)
  Product/1 -> F_Excitation/1  "F_Excitation"
  Add/1 -> Product/2  "F_wave"
  Time/1 -> If2/1, Ramp Function/1(Time), Nonlinear FK Force Variant Subsystem/1(In1), Linear Wave Excitation Force Variant Subsystem/1(In1)
  Merge1/1 -> Product/1  "R"
  Ramp Function Time/1 -> If2/2
  If2/2 -> No Ramp Function/Action
  If2/1 -> Ramp Function/Action
  Ramp Function/1(R) -> Merge1/1
  No Ramp Function/1(R) -> Merge1/2

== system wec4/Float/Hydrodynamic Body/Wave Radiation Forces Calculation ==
  Velocity : Inport
  Acceleration : Inport  Port=2
  Time : Inport  Port=3
  Added Mass Matrix : Constant  Value=body.hydroForce.fAddedMass
  Product1 : Product  Multiplication=Matrix(*)
  SS CI and Constant-Damping-CoeVariant Subsystem : Subsystem  Variant=on
  Transport Delay : TransportDelay  DelayTime=10e-8
  F_RadiationDamping : Outport
  F_AddedMass : Outport  Port=2
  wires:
  Time/1 -> SS CI and Constant-Damping-CoeVariant Subsystem/2(In2)
  Acceleration/1 -> Transport Delay/1
  Transport Delay/1 -> Product1/2
  SS CI and Constant-Damping-CoeVariant Subsystem/1(Out1) -> F_RadiationDamping/1  "F_RadiationDamping"
  Velocity/1 -> SS CI and Constant-Damping-CoeVariant Subsystem/1(In1)
  Product1/1 -> F_AddedMass/1  "F_AddedMass"
  Added Mass Matrix/1 -> Product1/1

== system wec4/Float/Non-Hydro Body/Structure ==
  Total Force : Inport
  Body Properties : sm_lib/Body Elements/Solid  InertiaType=Custom  Mass=body.mass  MassUnits=kg  CenterOfMass=[0 0 0]  CenterOfMassUnits=m  MomentsOfInertia=body.momOfInertia  MomentsOfInertiaUnits=kg*m^2  ProductsOfInertia=[0 0 0]  ProductsOfInertiaUnits=kg*m^2  DensityBased=on  Density=1000  DensityUnits=kg/(m^3)  DoExposeReferenceFrame=on  SerializedFrames=<Frames/>  GraphicType=FromGeometry  MarkerShape=Sphere  MarkerSize=10  MarkerSizeUnits=m  GraphicVisPropType=SimpleVisualProperties  GraphicDiffuseColor=body.viz.color  GraphicSpecularColor=[0.5 0.5 0.5 1.0]  GraphicAmbientColor=[0.15 0.15 0.15 1.0]  GraphicEmissiveColor=[0.0 0.0 0.0 1.0]  GraphicShininess=75  GraphicOpacity=body.viz.opacity  GeometryShape=FromFile  RectangleSize=[1 1]  RectangleSizeUnits=m  BrickDimensions=[1 1 1]  BrickDimensionUnits=m  CylinderRadius=1  CylinderRadiusUnits=m  CylinderLength=1  CylinderLengthUnits=m  SphereRadius=1  SphereRadiusUnits=m  EllipsoidRadii=[1 1 1]  EllipsoidRadiiUnits=m  ExtrusionCrossSection=[1 1; -1 1; -1 -1; 1 -1]  ExtrusionCrossSectionUnits=m  ExtrusionLength=1  ExtrusionLengthUnits=m  PolygonNumSides=3  PolygonOuterRadius=1  PolygonOuterRadiusUnits=m  ExtGeomFileType=STL  ExtGeomFileName=.\geometry\wec4_float.stl  ExtGeomFileUnits=m  RevolutionCrossSection=[1 1; 1 -1; 2 -1; 2 1]  RevolutionCrossSectionUnits=m  RevolutionExtent=Full  RevolutionAngle=180  RevolutionAngleUnits=deg
  External Force and Torque : sm_lib/Forces and Torques/External Force and Torque  ForceResolutionFrame=World  EnableForceX=off  EnableForceY=off  EnableForceZ=off  EnableForce=on  TorqueResolutionFrame=World  EnableTorqueX=off  EnableTorqueY=off  EnableTorqueZ=off  EnableTorque=on
  Motion Sensor : Subsystem
  Rigid Transform (Setup CG) : sm_lib/Frames and Transforms/Rigid Transform  TranslationMethod=Cartesian  TranslationStandardOffset=0  TranslationLengthUnit=m  TranslationStandardAxis=+Z  TranslationCartesianOffset=body.cg  TranslationROffset=0  TranslationROffsetUnits=m  TranslationZOffset=0  TranslationZOffsetUnits=m  TranslationThetaOffset=0  TranslationThetaOffsetUnits=deg  RotationMethod=None  RotationAngleUnits=rad  RotationStandardAxis=+Y  RotationAngle=0.05  RotationArbitraryAxis=[0.57735026918962584 0.57735026918962584 0.57735026918962584]  FollAlignAxisA=+X  BaseAlignAxisA=+Y  FollAlignAxisB=+Y  BaseAlignAxisB=+Z  RotationSequenceAxes=FollowerAxes  RotationSequence=XYX  RotationSequenceAngles=[0 0 0]  RotationSequenceAnglesUnits=deg  RotationMatrix=[1 0 0; 0 1 0; 0 0 1]
  Rigid Transform (Setup Initial Disp) : sm_lib/Frames and Transforms/Rigid Transform  TranslationMethod=Cartesian  TranslationStandardOffset=0  TranslationLengthUnit=m  TranslationStandardAxis=+Z  TranslationCartesianOffset=body.initDisp.initLinDisp  TranslationROffset=0  TranslationROffsetUnits=m  TranslationZOffset=0  TranslationZOffsetUnits=m  TranslationThetaOffset=0  TranslationThetaOffsetUnits=deg  RotationMethod=ArbitraryAxis  RotationAngleUnits=rad  RotationStandardAxis=+Y  RotationAngle=body.initDisp.initAngularDispAngle  RotationArbitraryAxis=body.initDisp.initAngularDispAxis  FollAlignAxisA=+X  BaseAlignAxisA=+Y  FollAlignAxisB=+Y  BaseAlignAxisB=+Z  RotationSequenceAxes=FollowerAxes  RotationSequence=XYX  RotationSequenceAngles=[0 0 0]  RotationSequenceAnglesUnits=deg  RotationMatrix=[1 0 0; 0 1 0; 0 0 1]
  Selector : Selector  InputPortWidth=6  IndexOptions=Index vector (dialog)  Indices=[1:3]  OutputSizes=1
  Selector1 : Selector  InputPortWidth=6  IndexOptions=Index vector (dialog)  Indices=[4:6]  OutputSizes=1
  Simulink-PS Converter1 : nesl_utility/Simulink-PS Converter  PhysicalDomain=network_engine_domain  SubClassName=ps_input  LeftPortType=input  RightPortType=output  PseudoPeriodic=off  Frequencies=[]  NoiseDistribution=none  NoiseParameters=[]  Unit=1  AffineConversion=off  InputFiltering=off  SimscapeFilterOrder=1  InputFilterTimeConstant=0.001  UdotUserProvided=1
  Simulink-PS Converter2 : nesl_utility/Simulink-PS Converter  PhysicalDomain=network_engine_domain  SubClassName=ps_input  LeftPortType=input  RightPortType=output  PseudoPeriodic=off  Frequencies=[]  NoiseDistribution=none  NoiseParameters=[]  Unit=1  AffineConversion=off  InputFiltering=off  SimscapeFilterOrder=1  InputFilterTimeConstant=0.001  UdotUserProvided=1
  World Frame : sm_lib/Frames and Transforms/World Frame
  Conn Free Surface : PMIOPort  Port=1  Side=Right
  Response : Outport
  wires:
  Total Force/1 -> Selector1/1, Selector/1
  Selector/1 -> Simulink-PS Converter1/1
  Selector1/1 -> Simulink-PS Converter2/1
  Motion Sensor/1(Response) -> Response/1
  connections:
  External Force and Torque/LConn1 -- Simulink-PS Converter1/RConn1
  External Force and Torque/LConn2 -- Simulink-PS Converter2/RConn1
  Rigid Transform (Setup Initial Disp)/RConn1 -- Body Properties/RConn1 -- External Force and Torque/RConn1 -- Motion Sensor/RConn1
  Conn Free Surface/RConn1 -- Rigid Transform (Setup CG)/LConn1
  Rigid Transform (Setup Initial Disp)/LConn1 -- Rigid Transform (Setup CG)/RConn1
  World Frame/RConn1 -- Motion Sensor/LConn1

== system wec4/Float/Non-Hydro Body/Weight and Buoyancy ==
  Add1 : Sum  Inputs=+-
  Assignment (Add Net Bouyancy Force to Z-Direction) : Assignment  IndexOptions=Index vector (dialog)  Indices=3  OutputSizes=1
  Body Mass : Constant  Value=body.mass
  Constant1 : Constant  Value=[0 0 0 0 0 0]
  Gravity : Constant  Value=simu.g
  Product : Product
  Product1 : Product  Inputs=3
  Volume : Constant  Value=body.dispVol
  Water Density : Constant  Value=simu.rho
  Out1 : Outport
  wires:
  Add1/1 -> Assignment (Add Net Bouyancy Force to Z-Direction)/2
  Product1/1 -> Add1/2  "F_Buoyancy"
  Product/1 -> Add1/1  "F_Gravity"
  Water Density/1 -> Product1/1  "rho"
  Gravity/1 -> Product/1, Product1/2  "g"
  Volume/1 -> Product1/3  "Vol"
  Assignment (Add Net Bouyancy Force to Z-Direction)/1 -> Out1/1  "F_Restoring"
  Constant1/1 -> Assignment (Add Net Bouyancy Force to Z-Direction)/1
  Body Mass/1 -> Product/2  "m"

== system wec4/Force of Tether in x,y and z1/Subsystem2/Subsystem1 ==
  Constant1 : Constant  Value=rCogFloater
  Constant2 : Constant  Value=rCogSpar
  Constant4 : Constant  Value=abs(rCogSpar-rCogFloater)
  Selector23 : Selector  InputPortWidth=6  IndexOptions=Index vector (dialog)  Indices=1  OutputSizes=1
  Selector24 : Selector  InputPortWidth=6  IndexOptions=Index vector (dialog)  Indices=2  OutputSizes=1
  Selector25 : Selector  InputPortWidth=6  IndexOptions=Index vector (dialog)  Indices=3  OutputSizes=1
  Selector26 : Selector  InputPortWidth=6  IndexOptions=Index vector (dialog)  Indices=1  OutputSizes=1
  Selector27 : Selector  InputPortWidth=6  IndexOptions=Index vector (dialog)  Indices=2  OutputSizes=1
  Selector28 : Selector  InputPortWidth=6  IndexOptions=Index vector (dialog)  Indices=3  OutputSizes=1
  Sum : Sum  Inputs=|-+
  Sum1 : Sum  Inputs=|-+
  Sum2 : Sum  Inputs=|-+
  Sum3 : Sum  Inputs=|++
  Sum4 : Sum  Inputs=|+-
  Sum5 : Sum  Inputs=|+-
  x_r : Outport
  y_r : Outport  Port=2
  z_r : Outport  Port=3
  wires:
  Selector25/1 -> Sum5/1
  Selector27/1 -> Sum1/2
  Selector28/1 -> Sum4/1
  Selector23/1 -> Sum/1
  Selector24/1 -> Sum1/1
  Selector26/1 -> Sum/2
  [disp2] -> Selector23/1, Selector24/1, Selector25/1
  [disp1] -> Selector28/1, Selector27/1, Selector26/1
  Sum1/1 -> y_r/1
  Sum/1 -> x_r/1
  Sum2/1 -> Sum3/1
  Constant4/1 -> Sum3/2
  Sum3/1 -> z_r/1
  Sum5/1 -> Sum2/1
  Constant1/1 -> Sum4/2
  Sum4/1 -> Sum2/2
  Constant2/1 -> Sum5/2

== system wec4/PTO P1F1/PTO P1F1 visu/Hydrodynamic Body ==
  Additional Linear Damping Force Calculation : Subsystem
  B2B Subsystem : Subsystem  Variant=on
  Bus Creator : BusCreator  Inputs=6
  Bus Creator1 : BusCreator  Inputs=3
  Bus Selector1 : BusSelector  OutputSignals=F_Excitation,F_RadiationDamping,F_AddedMass,F_Restoring,F_MorrisonAndViscous,F_LinearDamping
  Bus Selector2 : BusSelector  OutputSignals=disp,vel,acc
  Hydrostatic Restoring Force Calculation : Subsystem
  Morrison Element and ViscousDampingForceCalculation : Subsystem
  Nonlinear Wave Elevation : Subsystem  TreatAsAtomicUnit=on  SystemSampleTime=simu.dtNL
  Structure : Subsystem
  Sum : Sum  Inputs=+-----
  To Workspace : ToWorkspace  VariableName=body4_out  SaveFormat=Structure With Time  SampleTime=-1
  Wave Diffraction and Excitation Force Calculation : Subsystem
  Wave Radiation Forces Calculation : Subsystem
  Conn : PMIOPort  Port=1  Side=Right
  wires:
  Additional Linear Damping Force Calculation/1(F_LinearDamping) -> Bus Creator/6
  Bus Creator/1 -> Bus Selector1/1, Bus Creator1/3  "BUS(7): Forces"
  Bus Selector2/1 -> [disp4]  "<disp>"
  Bus Selector2/3 -> [acc4]  "<acc>"
  Bus Selector2/2 -> [vel4]  "<vel>"
  Structure/1(Response) -> Bus Creator1/1, Bus Selector2/1
  Sum/1 -> Bus Creator1/2, Structure/1(Total Force)  "F_Total"
  Bus Creator1/1 -> To Workspace/1
  Bus Selector1/4 -> Sum/4  "<F_Restoring>"
  Bus Selector1/3 -> Sum/3  "<F_AddedMass>"
  Bus Selector1/5 -> Sum/5  "<F_MorrisonAndViscous>"
  Bus Selector1/2 -> Sum/2  "<F_RadiationDamping>"
  Bus Selector1/1 -> Sum/1  "<F_Excitation>"
  Bus Selector1/6 -> Sum/6  "<F_LinearDamping>"
  [acc4] -> B2B Subsystem/2(acc_in), Morrison Element and ViscousDampingForceCalculation/2(Acceleration)
  [vel4] -> Morrison Element and ViscousDampingForceCalculation/3(Velocity), Additional Linear Damping Force Calculation/1(Velocity), B2B Subsystem/1(vel_in)
  B2B Subsystem/2(acc) -> Wave Radiation Forces Calculation/2(Acceleration)
  B2B Subsystem/1(vel) -> Wave Radiation Forces Calculation/1(Velocity)
  [disp4] -> Hydrostatic Restoring Force Calculation/1(Displacement), Morrison Element and ViscousDampingForceCalculation/1(Displacement), Nonlinear Wave Elevation/1(Displacement), Wave Diffraction and Excitation Force Calculation/2(Displacement)
  Nonlinear Wave Elevation/1(Wave Elevation) -> Wave Diffraction and Excitation Force Calculation/3(WaveElv), Hydrostatic Restoring Force Calculation/2(Wave Elv)
  Hydrostatic Restoring Force Calculation/1(F_Restoring) -> Bus Creator/4
  Wave Radiation Forces Calculation/1(F_RadiationDamping) -> Bus Creator/2
  Wave Diffraction and Excitation Force Calculation/1(F_Excitation) -> Bus Creator/1
  Wave Radiation Forces Calculation/2(F_AddedMass) -> Bus Creator/3
  [Clock] -> Nonlinear Wave Elevation/2(Time), Wave Diffraction and Excitation Force Calculation/1(Time), Morrison Element and ViscousDampingForceCalculation/4(Time), Wave Radiation Forces Calculation/3(Time)
  Morrison Element and ViscousDampingForceCalculation/1(F_MorrisonAndViscous) -> Bus Creator/5
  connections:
  Conn/RConn1 -- Structure/RConn1

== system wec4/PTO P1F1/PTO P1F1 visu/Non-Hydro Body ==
  Bus Creator : BusCreator  Inputs=6
  Bus Creator1 : BusCreator  Inputs=3
  Bus Selector1 : BusSelector  OutputSignals=F_Excitation,F_RadiationDamping,F_AddedMass,F_Restoring,F_MorrisonAndViscous,F_LinearDamping
  Constant{,1..3,5} (5 alike) : Constant  Value=[0 0 0 0 0 0]
  Structure : Subsystem
  Sum : Sum  Inputs=+-----
  To Workspace : ToWorkspace  VariableName=body4_out  SaveFormat=Structure With Time  SampleTime=-1
  Weight and Buoyancy : Subsystem
  Conn : PMIOPort  Port=1  Side=Right
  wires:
  Bus Creator/1 -> Bus Creator1/3, Bus Selector1/1  "BUS(7): Forces"
  Structure/1(Response) -> Bus Creator1/1
  Sum/1 -> Bus Creator1/2, Structure/1(Total Force)  "F_Total"
  Bus Creator1/1 -> To Workspace/1
  Bus Selector1/4 -> Sum/4  "<F_Restoring>"
  Bus Selector1/3 -> Sum/3  "<F_AddedMass>"
  Bus Selector1/5 -> Sum/5  "<F_MorrisonAndViscous>"
  Bus Selector1/2 -> Sum/2  "<F_RadiationDamping>"
  Bus Selector1/1 -> Sum/1  "<F_Excitation>"
  Bus Selector1/6 -> Sum/6  "<F_LinearDamping>"
  Constant5/1 -> Bus Creator/6  "F_LinearDamping"
  Constant3/1 -> Bus Creator/5  "F_MorrisonAndViscous"
  Constant2/1 -> Bus Creator/3  "F_AddedMass"
  Constant1/1 -> Bus Creator/2  "F_RadiationDamping"
  Constant/1 -> Bus Creator/1  "F_Excitation"
  Weight and Buoyancy/1(Out1) -> Bus Creator/4  "F_Restoring"
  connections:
  Conn/RConn1 -- Structure/RConn1

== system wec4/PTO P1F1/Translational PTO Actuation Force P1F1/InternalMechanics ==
  note: Calculate PTO force and power. F_pto = k*x + c*v, where F_pto is the force the PTO applies to the body (at the PTO location), x and v are the joint position and velocity. The power extracted is P = c * v^2
  Position : Inport
  Velocity : Inport  Port=2
  Add : Sum  Inputs=--
  Math Function : Math  Operator=square
  PCC Damping Coefficient : Constant  Value=pto.c
  PCC Stiffness Coefficient : Constant  Value=pto.k
  Product : Product  Inputs=**
  Product1 : Product  Inputs=**
  Product2 : Product  Inputs=**
  Force : Outport
  Power : Outport  Port=2
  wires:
  PCC Damping Coefficient/1 -> Product2/1, Product1/1
  Product2/1 -> Power/1
  Velocity/1 -> Math Function/1, Product1/2
  PCC Stiffness Coefficient/1 -> Product/2
  Position/1 -> Product/1
  Add/1 -> Force/1
  Math Function/1 -> Product2/2
  Product/1 -> Add/1
  Product1/1 -> Add/2
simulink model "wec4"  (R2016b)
settings: Solver=ode4  StartTime=0  StopTime=1000  FixedStep=0.005  MaxStep=0.005  RelTol=1e-3  EnableMultiTasking=on
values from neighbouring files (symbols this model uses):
  arAdaptiveLawData = 1/2*zModelSimple.zModelPto.arFreq.*     zModelSimple.zModelPto.arMagnitude./     cos(zModelSimple.zModelPto.arPhase*pi/180+pi/2)    [IMPACT_Control.m]
  arAdaptiveLawDataX = 1/2*zModelSimpleX.zModelPto.arFreq.*         zModelSimpleX.zModelPto.arMagnitude./         cos(zModelSimpleX.zModelPto.arPhase*pi/180+pi/2)    [IMPACT_Control.m]
  arControllerRampGain = [0,0,1,1]    [IMPACT_Control.m]
  arControllerRampTime = [0 rStartRampTime rStartRampTime+rRampTimeLength 8000]    [IMPACT_Control.m]
  arEkfInitialisation = zeros(1,11)    [IMPACT_Control.m]
  arEkfInitialisationX = zeros(1,11)    [IMPACT_Control.m]
  arFrequency = zModelSimple.zModelPto.arFreq    [IMPACT_Control.m]
  arFrequencyRange = zModelSimple.zModelPto.arFreq    [IMPACT_Control.m]
  arFrequencyX = zModelSimpleX.zModelPto.arFreq    [IMPACT_Control.m]
  arImpedance = 1./zModelSimple.zModelPto.arMagnitude./zModelSimple.zModelPto.arFreq    [IMPACT_Control.m]
  arImpedanceX = 1./zModelSimpleX.zModelPto.arMagnitude./zModelSimpleX.zModelPto.arFreq    [IMPACT_Control.m]
  CentralPTOPreload = -1.6113e+07    (= -16113000)    [wecSimInputFile.m]
  F1 = [4.243 2.375 -12.243]    [wecSimInputFile.m]
  F2 = [4.243 -2.375 -12.243]    [wecSimInputFile.m]
  F3 = [-4.243 -2.375 -12.243]    [wecSimInputFile.m]
  F4 = [-4.243 2.375 -12.243]    [wecSimInputFile.m]
  FC = [0 0 -14]    [wecSimInputFile.m]
  iAdaptiveDamping = 0    [wec4IMPACT_Project.m]    (also in IMPACT_Control.m = handles.iAdaptiveDamping; wec1_IMPACT_Project.m; wec2_IMPACT_Project.m; wec3_IMPACT_Project.m)
  iControlType = 2    [wec4IMPACT_Project.m]    (also in IMPACT_Control.m = handles.iControlType; wec1_IMPACT_Project.m = 1; wec2_IMPACT_Project.m = 1; wec3_IMPACT_Project.m = 1)
  iPtoPositionConstraint = 1    [wec4IMPACT_Project.m]    (also in IMPACT_Control.m = handles.iPtoPositionConstraint; wec1_IMPACT_Project.m = 0; wec2_IMPACT_Project.m; wec3_IMPACT_Project.m)
  iSensorNoise = 0    [IMPACT_Control.m]
  m = m+1    (= 2)    [checkParamFile.m]
  PTOrotation = atan((T1(2)-F1(2))/(T1(1)-F1(1)))    [wecSimInputFile.m]
  rCogFloater = -8    [wec4_IMPACT_Model.m]    (also in paramInitial.m = get( handles.edit_rCogFloater, 'String' ); wec1_IMPACT_Model.m = -18; wec2_IMPACT_Model.m = -8.5; wec3_IMPACT_Model.m = -0.7)
  rCogSpar = -36.6    [wec4_IMPACT_Model.m]    (also in paramInitial.m = get( handles.edit_rCogSpar, 'String' ); wec3_IMPACT_Model.m = -21.3; wec3_IMPACT_Model2.m = -21.3)
  rDisplacementLimit = 10.000000    (= 10)    [wec4IMPACT_Project.m]    (also in IMPACT_Control.m = getValue(handles.edit_displacementLimit); wec1_IMPACT_Project.m; wec2_IMPACT_Project.m; wec3_IMPACT_Project.m = 3)
  rDisplacementLimitX = 10.000000    (= 10)    [wec4IMPACT_Project.m]    (also in IMPACT_Control.m = getValue(handles.edit_displacementLimitX); wec1_IMPACT_Project.m = 0; wec2_IMPACT_Project.m; wec3_IMPACT_Project.m = 0)
  rGainForAntiWIndUp = tfControllerDiscrete.rGain    [IMPACT_Control.m]
  rGainForAntiWIndUpX = tfControllerXDiscrete.rGain    [IMPACT_Control.m]
  rMaxForcePto = 300000000.000000    (= 300000000)    [wec4IMPACT_Project.m]    (also in IMPACT_Control.m = getValue(handles.edit_maxForcePto); wec1_IMPACT_Project.m = 1e+15; wec2_IMPACT_Project.m = 1e+15; wec3_IMPACT_Project.m = 1000000000)
  rMinForcePto = -300000000.000000    (= -300000000)    [wec4IMPACT_Project.m]    (also in IMPACT_Control.m = getValue(handles.edit_minForcePto); wec1_IMPACT_Project.m = -1e+15; wec2_IMPACT_Project.m = -1e+15; wec3_IMPACT_Project.m = -1000000000)
  rMooringX = 20000    [wec4_IMPACT_Model.m]    (also in paramInitial.m = get( handles.edit_rMooringX, 'String' ); wec3_IMPACT_Model.m = 10000; wec3_IMPACT_Model2.m = 10000)
  rMooringZ = 10000    [wec4_IMPACT_Model.m]    (also in paramInitial.m = get( handles.edit_rMooringZ, 'String' ); wec3_IMPACT_Model.m = 0; wec3_IMPACT_Model2.m = 0)
  rOutputSampleTime = 0.010000    (= 0.01)    [wec4IMPACT_Project.m]    (also in IMPACT_Control.m = getValue(handles.edit_outputSampleTime); wec1_IMPACT_Project.m; wec2_IMPACT_Project.m; wec3_IMPACT_Project.m)
  rPassiveDampingGain = -604830.000000    (= -604830)    [wec4IMPACT_Project.m]    (also in IMPACT_Control.m = getValue(handles.edit_gainPLD); wec1_IMPACT_Project.m = -214018.1537; wec2_IMPACT_Project.m = -1948070; wec3_IMPACT_Project.m = -519390)
  rPassiveDampingGainX = -278660.000000    (= -278660)    [wec4IMPACT_Project.m]    (also in IMPACT_Control.m = getValue(handles.edit_gainPLDX); wec1_IMPACT_Project.m = 0; wec2_IMPACT_Project.m = 0; wec3_IMPACT_Project.m = 0)
  rTetherPretension = 1.6113e+07    (= 16113000)    [wec4_IMPACT_Model.m]    (also in paramInitial.m = get( handles.edit_rTetherPretension, 'String' ); wec3_IMPACT_Model.m = 0; wec3_IMPACT_Model2.m = 0)
  rTetherSpring = 500000    [wec4_IMPACT_Model.m]    (also in paramInitial.m = get( handles.edit_rTetherSpring, 'String' ); wec3_IMPACT_Model.m = 0; wec3_IMPACT_Model2.m = 0)
  rUpperFrequencyLimit = EKFFloater.upperFreq    [IMPACT_Control.m]
  rXf = 4.243    [wec4AdditionalParams.m]
  rXs = 16.075    [wec4AdditionalParams.m]
  rYf = 2.375    [wec4AdditionalParams.m]
  rYs = 16.075    [wec4AdditionalParams.m]
  rZf = 4.243    [wec4AdditionalParams.m]
  rZs = 2.4350    (= 2.435)    [wec4AdditionalParams.m]
  rZTetherF = 6    [wec4AdditionalParams.m]
  rZTetherS = 2.4350    (= 2.435)    [wec4AdditionalParams.m]
  s = tf('s')    [wec4_IMPACT_Model.m]    (also in IMPACT_Control.m; wec1_IMPACT_Model.m; wec2_IMPACT_Model.m; wec3_IMPACT_Model.m)
  SidePTO1Preload = PreloadPTOCorner    (= 0)    [wecSimInputFile.m]
  SidePTO2Preload = PreloadPTOCorner    (= 0)    [wecSimInputFile.m]
  SidePTO3Preload = PreloadPTOCorner    (= 0)    [wecSimInputFile.m]
  SidePTO4Preload = PreloadPTOCorner    (= 0)    [wecSimInputFile.m]
  simu = simulationClass()    [wecSimInputFile.m]
  T1 = [16.075 16.075 -34.165]    [wecSimInputFile.m]
  T2 = [16.075 -16.075 -34.165]    [wecSimInputFile.m]
  T3 = [-16.075 -16.075 -34.165]    [wecSimInputFile.m]
  T4 = [-16.075 16.075 -34.165]    [wecSimInputFile.m]
  TC = [0 0 -34.165]    [wecSimInputFile.m]
  waves = waveClass('irregular')    [wecSimInputFile.m]
  Z = magPhaseToComplex(zModelTf)    [IMPACT_Control.m]
undefined symbols (not defined in the file or in its folder): arControllerDiscreteDen, arControllerDiscreteNum, arControllerDiscreteXDen, arControllerDiscreteXNum, arExcForceFloaterDen, arExcForceFloaterNum, arExcForceFloaterXDen, arExcForceFloaterXNum, arExcForceSparDen, arExcForceSparNum, arExcForceSparXDen, arExcForceSparXNum, arFexcFloaterDen, arFexcFloaterNum, arFexcFloaterXDen, arFexcFloaterXNum, arFexcSparDen, arFexcSparNum, arFexcSparXDen, arFexcSparXNum, Body, body, constraint, CTTime, deg, Elements, geometry, IRKB, kg, lenJ, mooring, N, pto, rAccelerationGainFloater, rAccelerationGainFloaterX, rAccelerationGainSpar, rAccelerationGainSparX, rad, rBuoyancyGainFloater, rBuoyancyGainFloaterX, rBuoyancyGainSpar, rBuoyancyGainSparX, rDampingGainFloater, rDampingGainFloaterX, rDampingGainSpar, rDampingGainSparX, Rigid, rMaxFocePto, wec4_float, wec4_reactor, WECSim_Lib, X, Y
libraries: nesl_utility x380, sm_lib x170, vrlib x91, simulink x12, WECSim_Lib x4
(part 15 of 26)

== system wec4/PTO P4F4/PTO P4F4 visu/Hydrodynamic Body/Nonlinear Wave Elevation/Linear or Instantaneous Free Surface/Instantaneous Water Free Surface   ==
  In1 : Inport
  In2 : Inport  Port=2
  Center of Gravity : Constant  Value=body.cg
  Frequency Spacing : Constant  Value=waves.dw
  Instantaneous FS : MATLAB Function  TreatAsAtomicUnit=on
  Ramp Time : Constant  Value=simu.rampTime
  STL Centers : Constant  Value=body.bodyGeometry.center
  Wave Amplitude : Constant  Value=waves.A
  Wave Direction : Constant  Value=waves.waveDir
  Wave Frequency : Constant  Value=waves.w
  Wave Number : Constant  Value=waves.k
  Wave Random Phase : Constant  Value=waves.phase
  Wave Type Number : Constant  Value=waves.typeNum
  Out1 : Outport
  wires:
  Wave Amplitude/1 -> Instantaneous FS/4(AH)
  Wave Direction/1 -> Instantaneous FS/12(waveDir)
  In1/1 -> Instantaneous FS/1(x)
  In2/1 -> Instantaneous FS/9(t)
  Frequency Spacing/1 -> Instantaneous FS/6(dw)
  Wave Random Phase/1 -> Instantaneous FS/11(phaseRand)
  Ramp Time/1 -> Instantaneous FS/10(rampT)
  Wave Type Number/1 -> Instantaneous FS/8(typeNum)
  Wave Frequency/1 -> Instantaneous FS/5(w)
  Wave Number/1 -> Instantaneous FS/7(k)
  Center of Gravity/1 -> Instantaneous FS/3(cg)
  STL Centers/1 -> Instantaneous FS/2(center)
  Instantaneous FS/1(f) -> Out1/1

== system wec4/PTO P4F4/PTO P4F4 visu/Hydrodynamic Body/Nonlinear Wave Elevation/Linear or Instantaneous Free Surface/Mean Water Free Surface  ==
  zero : Constant  Value=0
  Out1 : Outport
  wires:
  zero/1 -> Out1/1

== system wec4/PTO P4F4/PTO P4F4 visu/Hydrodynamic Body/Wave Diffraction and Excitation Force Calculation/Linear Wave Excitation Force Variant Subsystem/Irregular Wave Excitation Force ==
  note: Calculates the wave force, F_wave, for the case of Irregular Waves. F_wave = sum( F_wave(i)) where i = each frequency bin.
  In1 : Inport
  Frequency Spacing Delta Omega : Constant  Value=waves.dw  VectorParams1D=off
  Imaginary Part of Wave Excitation : Constant  Value=body.hydroForce.fExt.im  VectorParams1D=off
  MATLAB Function : MATLAB Function  TreatAsAtomicUnit=on
  Random Phase : Constant  Value=waves.phase  VectorParams1D=off
  Real Part of Wave Excitation : Constant  Value=body.hydroForce.fExt.re  VectorParams1D=off
  Wave Frequency : Constant  Value=waves.w  VectorParams1D=off
  Wave Spectrum : Constant  Value=waves.A  VectorParams1D=off
  Out1 : Outport
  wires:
  Frequency Spacing Delta Omega/1 -> MATLAB Function/6(dw)
  In1/1 -> MATLAB Function/7(time)
  Wave Spectrum/1 -> MATLAB Function/1(A)
  Real Part of Wave Excitation/1 -> MATLAB Function/3(fExtRE)
  Imaginary Part of Wave Excitation/1 -> MATLAB Function/4(fExtIM)
  Wave Frequency/1 -> MATLAB Function/2(w)
  MATLAB Function/1(Fext) -> Out1/1
  Random Phase/1 -> MATLAB Function/5(phaseRand)

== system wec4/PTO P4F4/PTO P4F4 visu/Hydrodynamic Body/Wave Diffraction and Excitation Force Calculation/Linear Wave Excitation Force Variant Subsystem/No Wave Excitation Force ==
  Constant : Constant  Value=[0 0 0 0 0 0]
  Out1 : Outport
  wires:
  Constant/1 -> Out1/1

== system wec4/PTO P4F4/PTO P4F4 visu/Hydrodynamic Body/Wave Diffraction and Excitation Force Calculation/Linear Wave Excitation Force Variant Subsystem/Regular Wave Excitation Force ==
  note: Calculates the wave force, F_wave, for the case of Regular Waves. F_wave = A * cos(w * t) * Re{Fext} - A * sin(w * t) * Im{Fext}
  In1 : Inport
  Add : Sum
  Add1 : Sum  Inputs=+-
  Constant : Constant  Value=pi/2
  Excitation Imaginary Part : Constant  Value=body.hydroForce.fExt.im(1,:)  VectorParams1D=off
  Excitation Real Part : Constant  Value=body.hydroForce.fExt.re(1,:)  VectorParams1D=off
  Product : Product
  Product1 : Product  Inputs=3
  Product2 : Product  Inputs=3
  Sine Wave Function : Sin  TimeSource=Use external signal  SampleTime=0
  Sine Wave Function1 : Sin  TimeSource=Use external signal  SampleTime=0
  Wave Amplitude : Constant  Value=waves.A(1,:)
  Wave Frequency : Constant  Value=waves.w(1,:)
  Out1 : Outport
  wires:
  Constant/1 -> Add/2
  Add/1 -> Sine Wave Function1/1
  Wave Amplitude/1 -> Product1/1, Product2/1  "A"
  Add1/1 -> Out1/1
  Product2/1 -> Add1/2
  Product1/1 -> Add1/1
  Excitation Real Part/1 -> Product1/2  "Re{Fext}"
  Excitation Imaginary Part/1 -> Product2/3  "Im{Fext}"
  Sine Wave Function/1 -> Product2/2  "sin(wt)"
  Sine Wave Function1/1 -> Product1/3  "cos(w*t)"
  Product/1 -> Add/1, Sine Wave Function/1
  Wave Frequency/1 -> Product/2  "w"
  In1/1 -> Product/1  "t"

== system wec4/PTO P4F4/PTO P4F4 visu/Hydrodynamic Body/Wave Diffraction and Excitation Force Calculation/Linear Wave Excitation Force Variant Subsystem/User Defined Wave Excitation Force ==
  note: Calculates the wave force, F_wave, for the case of User Defined Waves. F_wave = convolution calculation [1x6]
  InputWaveForceTimeHistory : FromWorkspace  VariableName=[waves.waveAmpTime(:,1),body.hydroForce.userDefinedFe]  SampleTime=0
  Out1 : Outport
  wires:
  InputWaveForceTimeHistory/1 -> Out1/1

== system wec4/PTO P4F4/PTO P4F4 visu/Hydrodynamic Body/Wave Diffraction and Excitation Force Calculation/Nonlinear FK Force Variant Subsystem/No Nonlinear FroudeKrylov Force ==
  Constant : Constant  Value=[0 0 0 0 0 0]
  Out1 : Outport
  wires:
  Constant/1 -> Out1/1

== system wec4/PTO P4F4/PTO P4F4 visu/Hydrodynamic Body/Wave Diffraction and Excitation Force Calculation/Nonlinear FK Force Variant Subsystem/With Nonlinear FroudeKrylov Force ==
  In1 : Inport
  In2 : Inport  Port=2
  In3 : Inport  Port=3
  Add : Sum  Inputs=+-
  Center of Gravity : Constant  Value=body.hydroData.properties.cg
  Center of Gravity1 : Constant  Value=body.hydroData.properties.cg
  Constant : Constant  Value=[0 0 0]
  Deep Water Flag : Constant  Value=waves.deepWaterWave
  Diffraction and Excitation Forces : MATLAB Function  TreatAsAtomicUnit=on
  Frequency Spacing : Constant  Value=waves.dw
  Gravity : Constant  Value=simu.g
  Mux : Mux  Inputs=2
  STL Areas : Constant  Value=body.bodyGeometry.area
  STL Centers : Constant  Value=body.bodyGeometry.center
  STL Normal Vectors : Constant  Value=body.bodyGeometry.norm
  To Workspace : ToWorkspace  VariableName=body7_wavenonlinearpressure_out  SaveFormat=Structure With Time  SampleTime=-1
  To Workspace1 : ToWorkspace  VariableName=body7_wavelinearpressure_out  SaveFormat=Structure With Time  SampleTime=-1
  Water Density : Constant  Value=simu.rho
  Water Depth : Constant  Value=waves.waterDepth
  Wave Amplitude : Constant  Value=waves.A
  Wave Frequency : Constant  Value=waves.w
  Wave Number : Constant  Value=waves.k
  Wave Random Phase : Constant  Value=waves.phase
  Wave Type Number : Constant  Value=waves.typeNum
  Out1 : Outport
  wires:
  STL Areas/1 -> Diffraction and Excitation Forces/5(area)
  Diffraction and Excitation Forces/2(wp) -> To Workspace/1
  Diffraction and Excitation Forces/3(wpMeanFS) -> To Workspace1/1
  In2/1 -> Add/1
  Constant/1 -> Mux/2
  Center of Gravity/1 -> Mux/1  "cg"
  Mux/1 -> Add/2
  Add/1 -> Diffraction and Excitation Forces/1(x)  "x_cg"
  Deep Water Flag/1 -> Diffraction and Excitation Forces/13(deepWaterWave)
  Wave Random Phase/1 -> Diffraction and Excitation Forces/17(phaseRand)
  Water Depth/1 -> Diffraction and Excitation Forces/12(wDepth)
  Wave Number/1 -> Diffraction and Excitation Forces/14(k)
  Wave Type Number/1 -> Diffraction and Excitation Forces/15(typeNum)
  Frequency Spacing/1 -> Diffraction and Excitation Forces/11(dw)
  Wave Frequency/1 -> Diffraction and Excitation Forces/10(w)
  Wave Amplitude/1 -> Diffraction and Excitation Forces/9(AH)
  In1/1 -> Diffraction and Excitation Forces/16(t)
  In3/1 -> Diffraction and Excitation Forces/2(elv)
  STL Centers/1 -> Diffraction and Excitation Forces/3(center)
  STL Normal Vectors/1 -> Diffraction and Excitation Forces/4(tnorm)
  Water Density/1 -> Diffraction and Excitation Forces/6(rho)
  Gravity/1 -> Diffraction and Excitation Forces/7(g)
  Diffraction and Excitation Forces/1(f) -> Out1/1
  Center of Gravity1/1 -> Diffraction and Excitation Forces/8(cg)

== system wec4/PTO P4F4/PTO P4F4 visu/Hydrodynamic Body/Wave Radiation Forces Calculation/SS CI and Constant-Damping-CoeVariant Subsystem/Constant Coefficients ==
  In1 : Inport
  Product : Product  Multiplication=Matrix(*)
  Radiation Damping Matrix : Constant  Value=body.hydroForce.fDamping
  Out1 : Outport
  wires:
  In1/1 -> Product/2
  Product/1 -> Out1/1  "F_Single Frequency"
  Radiation Damping Matrix/1 -> Product/1

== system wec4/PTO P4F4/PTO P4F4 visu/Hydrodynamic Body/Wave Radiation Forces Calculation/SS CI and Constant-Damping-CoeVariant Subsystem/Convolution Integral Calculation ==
  In1 : Inport
  MATLAB Function : MATLAB Function  TreatAsAtomicUnit=on  SystemSampleTime=simu.CTTime(2) - simu.CTTime(1)
  Rate Transition : RateTransition
  Reshape : Reshape
  Out1 : Outport
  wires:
  Rate Transition/1 -> Reshape/1
  MATLAB Function/1(F_FM) -> Rate Transition/1
  Reshape/1 -> Out1/1
  In1/1 -> MATLAB Function/1(v)

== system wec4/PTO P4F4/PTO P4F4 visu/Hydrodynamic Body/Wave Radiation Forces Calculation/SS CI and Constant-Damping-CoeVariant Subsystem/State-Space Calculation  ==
  In1 : Inport
  State-Space : StateSpace  A=body.hydroForce.ssRadf.A  B=body.hydroForce.ssRadf.B  C=body.hydroForce.ssRadf.C  D=body.hydroForce.ssRadf.D  X0=0
  Out1 : Outport
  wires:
  State-Space/1 -> Out1/1
  In1/1 -> State-Space/1  "x"

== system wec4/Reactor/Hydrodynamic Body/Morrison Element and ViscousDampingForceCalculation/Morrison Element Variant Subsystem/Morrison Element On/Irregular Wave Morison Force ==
  displacement : Inport
  velocity : Inport  Port=2
  acceleration : Inport  Port=3
  time : Inport  Port=4
  Area : Constant  Value=body.morrisonElement.characteristicArea  VectorParams1D=off
  Ca : Constant  Value=body.morrisonElement.ca  VectorParams1D=off
  Cd : Constant  Value=body.morrisonElement.cd  VectorParams1D=off
  MESum : Sum  Inputs=+  CollapseMode=Specified dimension
  MorrisonElements : Subsystem  TreatAsAtomicUnit=on
  Reshape : Reshape
  Volume : Constant  Value=body.morrisonElement.VME  VectorParams1D=off
  "r_{g}" : Constant  Value=body.morrisonElement.rgME  VectorParams1D=off
  morison_force : Outport
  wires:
  time/1 -> MorrisonElements/9(Time)
  MESum/1 -> Reshape/1
  Reshape/1 -> morison_force/1
  MorrisonElements/1(Force) -> MESum/1
  Ca/1 -> MorrisonElements/8(Ca)
  Volume/1 -> MorrisonElements/7(Vol)
  acceleration/1 -> MorrisonElements/3(Accel)
  displacement/1 -> MorrisonElements/4(Disp)
  Cd/1 -> MorrisonElements/6(Cd)
  Area/1 -> MorrisonElements/5(A)
  "r_{g}"/1 -> MorrisonElements/1(r)
  velocity/1 -> MorrisonElements/2(Vel)

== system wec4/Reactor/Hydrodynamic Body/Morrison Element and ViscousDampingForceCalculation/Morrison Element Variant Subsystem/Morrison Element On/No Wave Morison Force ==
  displacement : Inport
  velocity : Inport  Port=2
  acceleration : Inport  Port=3
  time : Inport  Port=4
  Area : Constant  Value=body.morrisonElement.characteristicArea  VectorParams1D=off
  Ca : Constant  Value=body.morrisonElement.ca  VectorParams1D=off
  Cd : Constant  Value=body.morrisonElement.cd  VectorParams1D=off
  MESum : Sum  Inputs=+  CollapseMode=Specified dimension
  MorrisonElements : Subsystem  TreatAsAtomicUnit=on
  Reshape : Reshape
  Volume : Constant  Value=body.morrisonElement.VME  VectorParams1D=off
  "r_{g}" : Constant  Value=body.morrisonElement.rgME  VectorParams1D=off
  morison_force : Outport
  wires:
  time/1 -> MorrisonElements/9(Time)
  Reshape/1 -> morison_force/1
  MESum/1 -> Reshape/1
  acceleration/1 -> MorrisonElements/3(Accel)
  velocity/1 -> MorrisonElements/2(Vel)
  displacement/1 -> MorrisonElements/4(Disp)
  Ca/1 -> MorrisonElements/8(Ca)
  Volume/1 -> MorrisonElements/7(Vol)
  MorrisonElements/1(Force) -> MESum/1
  Cd/1 -> MorrisonElements/6(Cd)
  Area/1 -> MorrisonElements/5(Area)
  "r_{g}"/1 -> MorrisonElements/1(r)

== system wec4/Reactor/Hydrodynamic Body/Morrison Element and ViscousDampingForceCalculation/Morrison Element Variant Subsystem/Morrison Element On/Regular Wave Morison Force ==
  displacement : Inport
  velocity : Inport  Port=2
  acceleration : Inport  Port=3
  time : Inport  Port=4
  Area : Constant  Value=body.morrisonElement.characteristicArea  VectorParams1D=off
  Ca : Constant  Value=body.morrisonElement.ca  VectorParams1D=off
  Cd : Constant  Value=body.morrisonElement.cd  VectorParams1D=off
  MESum : Sum  Inputs=+  CollapseMode=Specified dimension
  MorrisonElements : Subsystem  TreatAsAtomicUnit=on
  Reshape : Reshape
  Volume : Constant  Value=body.morrisonElement.VME  VectorParams1D=off
  "r_{g}" : Constant  Value=body.morrisonElement.rgME  VectorParams1D=off
  morison_force : Outport
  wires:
  time/1 -> MorrisonElements/9(Time)
  Reshape/1 -> morison_force/1
  MESum/1 -> Reshape/1
  acceleration/1 -> MorrisonElements/3(Accel)
  velocity/1 -> MorrisonElements/2(Vel)
  displacement/1 -> MorrisonElements/4(Disp)
  Ca/1 -> MorrisonElements/8(Ca)
  Volume/1 -> MorrisonElements/7(Vol)
  MorrisonElements/1(Force) -> MESum/1
  Cd/1 -> MorrisonElements/6(Cd)
  Area/1 -> MorrisonElements/5(Area)
  "r_{g}"/1 -> MorrisonElements/1(r)

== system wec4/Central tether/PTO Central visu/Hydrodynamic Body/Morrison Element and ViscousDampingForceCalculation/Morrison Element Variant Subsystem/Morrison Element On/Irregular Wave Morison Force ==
  displacement : Inport
  velocity : Inport  Port=2
  acceleration : Inport  Port=3
  time : Inport  Port=4
  Area : Constant  Value=body.morrisonElement.characteristicArea  VectorParams1D=off
  Ca : Constant  Value=body.morrisonElement.ca  VectorParams1D=off
  Cd : Constant  Value=body.morrisonElement.cd  VectorParams1D=off
  MESum : Sum  Inputs=+  CollapseMode=Specified dimension
  MorrisonElements : Subsystem  TreatAsAtomicUnit=on
  Reshape : Reshape
  Volume : Constant  Value=body.morrisonElement.VME  VectorParams1D=off
  "r_{g}" : Constant  Value=body.morrisonElement.rgME  VectorParams1D=off
  morison_force : Outport
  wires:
  time/1 -> MorrisonElements/9(Time)
  MESum/1 -> Reshape/1
  Reshape/1 -> morison_force/1
  MorrisonElements/1(Force) -> MESum/1
  Ca/1 -> MorrisonElements/8(Ca)
  Volume/1 -> MorrisonElements/7(Vol)
  acceleration/1 -> MorrisonElements/3(Accel)
  displacement/1 -> MorrisonElements/4(Disp)
  Cd/1 -> MorrisonElements/6(Cd)
  Area/1 -> MorrisonElements/5(A)
  "r_{g}"/1 -> MorrisonElements/1(r)
  velocity/1 -> MorrisonElements/2(Vel)

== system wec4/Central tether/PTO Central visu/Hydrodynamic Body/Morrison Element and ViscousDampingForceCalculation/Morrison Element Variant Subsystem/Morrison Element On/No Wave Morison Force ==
  displacement : Inport
  velocity : Inport  Port=2
  acceleration : Inport  Port=3
  time : Inport  Port=4
  Area : Constant  Value=body.morrisonElement.characteristicArea  VectorParams1D=off
  Ca : Constant  Value=body.morrisonElement.ca  VectorParams1D=off
  Cd : Constant  Value=body.morrisonElement.cd  VectorParams1D=off
  MESum : Sum  Inputs=+  CollapseMode=Specified dimension
  MorrisonElements : Subsystem  TreatAsAtomicUnit=on
  Reshape : Reshape
  Volume : Constant  Value=body.morrisonElement.VME  VectorParams1D=off
  "r_{g}" : Constant  Value=body.morrisonElement.rgME  VectorParams1D=off
  morison_force : Outport
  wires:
  time/1 -> MorrisonElements/9(Time)
  Reshape/1 -> morison_force/1
  MESum/1 -> Reshape/1
  acceleration/1 -> MorrisonElements/3(Accel)
  velocity/1 -> MorrisonElements/2(Vel)
  displacement/1 -> MorrisonElements/4(Disp)
  Ca/1 -> MorrisonElements/8(Ca)
  Volume/1 -> MorrisonElements/7(Vol)
  MorrisonElements/1(Force) -> MESum/1
  Cd/1 -> MorrisonElements/6(Cd)
  Area/1 -> MorrisonElements/5(Area)
  "r_{g}"/1 -> MorrisonElements/1(r)

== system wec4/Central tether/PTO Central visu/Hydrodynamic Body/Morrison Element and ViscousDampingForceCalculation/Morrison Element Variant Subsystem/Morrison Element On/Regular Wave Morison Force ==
  displacement : Inport
  velocity : Inport  Port=2
  acceleration : Inport  Port=3
  time : Inport  Port=4
  Area : Constant  Value=body.morrisonElement.characteristicArea  VectorParams1D=off
  Ca : Constant  Value=body.morrisonElement.ca  VectorParams1D=off
  Cd : Constant  Value=body.morrisonElement.cd  VectorParams1D=off
  MESum : Sum  Inputs=+  CollapseMode=Specified dimension
  MorrisonElements : Subsystem  TreatAsAtomicUnit=on
  Reshape : Reshape
  Volume : Constant  Value=body.morrisonElement.VME  VectorParams1D=off
  "r_{g}" : Constant  Value=body.morrisonElement.rgME  VectorParams1D=off
  morison_force : Outport
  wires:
  time/1 -> MorrisonElements/9(Time)
  Reshape/1 -> morison_force/1
  MESum/1 -> Reshape/1
  acceleration/1 -> MorrisonElements/3(Accel)
  velocity/1 -> MorrisonElements/2(Vel)
  displacement/1 -> MorrisonElements/4(Disp)
  Ca/1 -> MorrisonElements/8(Ca)
  Volume/1 -> MorrisonElements/7(Vol)
  MorrisonElements/1(Force) -> MESum/1
  Cd/1 -> MorrisonElements/6(Cd)
  Area/1 -> MorrisonElements/5(Area)
  "r_{g}"/1 -> MorrisonElements/1(r)

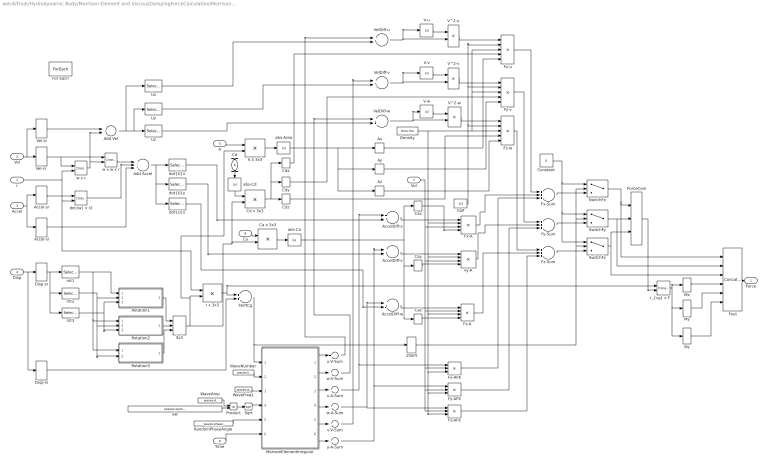
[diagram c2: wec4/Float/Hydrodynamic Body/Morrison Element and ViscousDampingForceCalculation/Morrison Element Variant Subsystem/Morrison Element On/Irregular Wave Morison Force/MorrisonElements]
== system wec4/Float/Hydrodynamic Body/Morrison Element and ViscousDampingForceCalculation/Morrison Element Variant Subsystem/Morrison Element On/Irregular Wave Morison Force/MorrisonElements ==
  r : Inport  Partition=on  PartitionDimension=1  PartitionWidth=1
  Vel : Inport  Port=2
  Accel : Inport  Port=3
  Disp : Inport  Port=4
  A : Inport  Port=5  Partition=on  PartitionDimension=1  PartitionWidth=1
  Cd : Inport  Port=6  Partition=on  PartitionDimension=1  PartitionWidth=1
  Vol : Inport  Port=7  Partition=on  PartitionDimension=1  PartitionWidth=1
  Ca : Inport  Port=8  Partition=on  PartitionDimension=1  PartitionWidth=1
  Time : Inport  Port=9
  3x3 : Concatenate  NumInputs=3  Mode=Multidimensional array
  A x 3x3 : Product  Multiplication=Matrix(*)
  Accel-sl : Selector  InputPortWidth=6  IndexOptions=Index vector (dialog)  Indices=[1 2 3]  OutputSizes=1
  Accel-sr : Selector  InputPortWidth=6  IndexOptions=Index vector (dialog)  Indices=[4 5 6]  OutputSizes=1
  AccelDiff-v : Sum  Inputs=+-
  AccelDiff-w : Sum  Inputs=+-
  AccelDiff-x : Sum  Inputs=+-
  Add Accel : Sum  Inputs=+++
  Add Vel : Sum
  Ax : Selector  InputPortWidth=3  IndexOptions=Index vector (dialog)  Indices=[1]  OutputSizes=1
  Ay : Selector  InputPortWidth=3  IndexOptions=Index vector (dialog)  Indices=[2]  OutputSizes=1
  Az : Selector  InputPortWidth=3  IndexOptions=Index vector (dialog)  Indices=[3]  OutputSizes=1
  Ca x 3x3 : Product  Multiplication=Matrix(*)
  Cax : Selector  InputPortWidth=3  IndexOptions=Index vector (dialog)  Indices=[1]  OutputSizes=1
  Cay : Selector  InputPortWidth=3  IndexOptions=Index vector (dialog)  Indices=[2]  OutputSizes=1
  Caz : Selector  InputPortWidth=3  IndexOptions=Index vector (dialog)  Indices=[3]  OutputSizes=1
  Cd x 3x3 : Product  Multiplication=Matrix(*)
  Cdx : Selector  InputPortWidth=3  IndexOptions=Index vector (dialog)  Indices=[1]  OutputSizes=1
  Cdy : Selector  InputPortWidth=3  IndexOptions=Index vector (dialog)  Indices=[2]  OutputSizes=1
  Cdz : Selector  InputPortWidth=3  IndexOptions=Index vector (dialog)  Indices=[3]  OutputSizes=1
  Constant : Constant  Value=0
  Density : Constant  Value=simu.rho
  Disp-sl : Selector  InputPortWidth=6  IndexOptions=Index vector (dialog)  Indices=[1 2 3]  OutputSizes=1
  Disp-sr : Selector  InputPortWidth=6  IndexOptions=Index vector (dialog)  Indices=[4 5 6]  OutputSizes=1
  For Each : ForEach  DisableCoverage=on  IndexMode=One-based
  ForceCom : Concatenate  NumInputs=3  ConcatenateDimension=2
  Fout : Concatenate  NumInputs=6  Mode=Multidimensional array  ConcatenateDimension=2
  Fx-A : Product  Inputs=4
  Fx-AFK : Product  Inputs=3
  Fx-Sum : Sum  Inputs=+++
  Fx-u : Product  Inputs=5
  Fy-A : Product  Inputs=4
  Fy-AFK : Product  Inputs=3
  Fy-Sum : Sum  Inputs=+++
  Fy-v : Product  Inputs=5
  Fz-A : Product  Inputs=4
  Fz-AFK : Product  Inputs=3
  Fz-Sum : Sum  Inputs=+++
  Fz-w : Product  Inputs=5
  MorisonElementIrregular : Subsystem  TreatAsAtomicUnit=on
  Mx : Selector  InputPortWidth=3  IndexOptions=Index vector (dialog)  Indices=[1]  OutputSizes=1
  My : Selector  InputPortWidth=3  IndexOptions=Index vector (dialog)  Indices=[2]  OutputSizes=1
  Mz : Selector  InputPortWidth=3  IndexOptions=Index vector (dialog)  Indices=[3]  OutputSizes=1
  Product : Product
  RandomPhaseAngle : Constant  Value=waves.phase  VectorParams1D=off
  Rotation1 : Subsystem
  Rotation2 : Subsystem
  Rotation3 : Subsystem
  ShiftCg : Sum
  Sqrt : Sqrt
  SwitchFx : Switch  Criteria=u2 > Threshold
  SwitchFy : Switch  Criteria=u2 > Threshold
  SwitchFz : Switch  Criteria=u2 > Threshold
  Ux : Selector  InputPortWidth=3  IndexOptions=Index vector (dialog)  Indices=[1]  OutputSizes=1
  Uy : Selector  InputPortWidth=3  IndexOptions=Index vector (dialog)  Indices=[2]  OutputSizes=1
  Uz : Selector  InputPortWidth=3  IndexOptions=Index vector (dialog)  Indices=[3]  OutputSizes=1
  V-u : Abs
  V-v : Abs
  V-w : Abs
  V^2-u : Product
  V^2-v : Product
  V^2-w : Product
  Vel-sl : Selector  InputPortWidth=6  IndexOptions=Index vector (dialog)  Indices=[1 2 3]  OutputSizes=1
  "Vel-sr " : Selector  InputPortWidth=6  IndexOptions=Index vector (dialog)  Indices=[4 5 6]  OutputSizes=1
  VelDiff-u : Sum  Inputs=+-
  VelDiff-v : Sum  Inputs=+-
  VelDiff-w : Sum  Inputs=+-
  WaveAmp : Constant  Value=waves.A  VectorParams1D=off
  WaveFreq1 : Constant  Value=waves.w  VectorParams1D=off
  WaveNumber : Constant  Value=waves.k  VectorParams1D=off
  Zshift : Selector  InputPortWidth=3  IndexOptions=Index vector (dialog)  Indices=[3]  OutputSizes=1
  abs-Area : Abs
  abs-Ca : Abs
  abs-Cd : Abs
  "dot{U}x" : Selector  InputPortWidth=3  IndexOptions=Index vector (dialog)  Indices=[1]  OutputSizes=1
  "dot{U}y" : Selector  InputPortWidth=3  IndexOptions=Index vector (dialog)  Indices=[2]  OutputSizes=1
  "dot{U}z" : Selector  InputPortWidth=3  IndexOptions=Index vector (dialog)  Indices=[3]  OutputSizes=1
  "dot{w} x r2" : vrlib/Utilities/Cross Product
  dw : Constant  Value=(waves.w(end)-waves.w(1))/(waves.numFreq-1)  VectorParams1D=off
  half : Constant  Value=1/2
  r x 3x3 : Product  Multiplication=Matrix(*)
  "r_{cg} x F" : vrlib/Utilities/Cross Product
  rot1 : Selector  InputPortWidth=3  IndexOptions=Index vector (dialog)  Indices=[1]  OutputSizes=1
  rot2 : Selector  InputPortWidth=3  IndexOptions=Index vector (dialog)  Indices=[2]  OutputSizes=1
  rot3 : Selector  InputPortWidth=3  IndexOptions=Index vector (dialog)  Indices=[3]  OutputSizes=1
  u-V-Sum : Sum  Inputs=+  CollapseMode=Specified dimension
  v-V-Sum : Sum  Inputs=+  CollapseMode=Specified dimension
  w x r : vrlib/Utilities/Cross Product
  w x w x r : vrlib/Utilities/Cross Product
  w-A-Sum : Sum  Inputs=+  CollapseMode=Specified dimension
  w-V-Sum : Sum  Inputs=+  CollapseMode=Specified dimension
  x-A-Sum : Sum  Inputs=+  CollapseMode=Specified dimension
  y-A-Sum : Sum  Inputs=+  CollapseMode=Specified dimension
  Force : Outport  PortDimensions=[1 6]  ConcatenationDimension=1
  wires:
  Time/1 -> MorisonElementIrregular/6(Time)
  abs-Cd/1 -> Cd x 3x3/1
  abs-Ca/1 -> Cay/1, Caz/1, Cax/1
  Fy-AFK/1 -> Fy-Sum/3
  Fy-A/1 -> Fy-Sum/2
  AccelDiff-v/1 -> Fy-A/1
  Cay/1 -> Fy-A/4
  y-A-Sum/1 -> AccelDiff-v/1, Fy-AFK/1
  Fy-v/1 -> Fy-Sum/1
  Fy-Sum/1 -> SwitchFy/3
  SwitchFy/1 -> ForceCom/2, Fout/2
  Cdy/1 -> Fy-v/4
  Ay/1 -> Fy-v/5
  V^2-v/1 -> Fy-v/1
  v-V-Sum/1 -> VelDiff-v/1
  V-v/1 -> V^2-v/1
  VelDiff-v/1 -> V^2-v/2, V-v/1
  V-w/1 -> V^2-w/1
  MorisonElementIrregular/6(y-A) -> y-A-Sum/1
  MorisonElementIrregular/5(v-V) -> v-V-Sum/1
  V-u/1 -> V^2-u/1
  MorisonElementIrregular/4(w-A) -> w-A-Sum/1
  MorisonElementIrregular/3(x-A) -> x-A-Sum/1
  MorisonElementIrregular/2(w-V) -> w-V-Sum/1
  Sqrt/1 -> MorisonElementIrregular/4(waves.A)
  Product/1 -> Sqrt/1
  dw/1 -> Product/2
  WaveAmp/1 -> Product/1
  MorisonElementIrregular/1(u-V) -> u-V-Sum/1
  RandomPhaseAngle/1 -> MorisonElementIrregular/5(waves.Phase)
  WaveFreq1/1 -> MorisonElementIrregular/3(waves.w)
  WaveNumber/1 -> MorisonElementIrregular/2(waves.kirr)
  Ca x 3x3/1 -> abs-Ca/1
  Ca/1 -> Ca x 3x3/1
  Cd x 3x3/1 -> Cdx/1, Cdy/1, Cdz/1
  Cd/1 -> abs-Cd/1
  Cax/1 -> Fx-A/4
  Caz/1 -> Fz-A/4
  Fout/1 -> Force/1
  ForceCom/1 -> "r_{cg} x F"/2
  abs-Area/1 -> Ax/1, Az/1, Ay/1
  A x 3x3/1 -> abs-Area/1
  Cdz/1 -> Fz-w/4
  Cdx/1 -> Fx-u/4
  Ax/1 -> Fx-u/5
  A/1 -> A x 3x3/1
  Az/1 -> Fz-w/5
  Fz-Sum/1 -> SwitchFz/3
  Fx-Sum/1 -> SwitchFx/3
  SwitchFx/1 -> ForceCom/1, Fout/1
  SwitchFz/1 -> Fout/3, ForceCom/3
  Zshift/1 -> SwitchFz/2, SwitchFx/2, SwitchFy/2
  VelDiff-u/1 -> V^2-u/2, V-u/1
  3x3/1 -> Cd x 3x3/2, Ca x 3x3/2, r x 3x3/2, A x 3x3/2
  Mz/1 -> Fout/6
  My/1 -> Fout/5
  Mx/1 -> Fout/4
  "r_{cg} x F"/1 -> Mx/1, My/1, Mz/1
  Constant/1 -> SwitchFx/1, SwitchFz/1, SwitchFy/1
  Fz-AFK/1 -> Fz-Sum/3
  Fz-A/1 -> Fz-Sum/2
  Fz-w/1 -> Fz-Sum/1
  Fx-AFK/1 -> Fx-Sum/3
  Fx-A/1 -> Fx-Sum/2
  Fx-u/1 -> Fx-Sum/1
  w-A-Sum/1 -> Fz-AFK/1, AccelDiff-w/1
  AccelDiff-w/1 -> Fz-A/1
  Vol/1 -> Fx-A/3, Fz-A/2, Fx-AFK/2, Fz-AFK/2, Fy-AFK/2, Fy-A/3
  AccelDiff-x/1 -> Fx-A/1
  V^2-w/1 -> Fz-w/1
  Density/1 -> Fz-w/3, Fx-u/3, Fy-v/3, Fx-A/2, Fz-A/3, Fx-AFK/3, Fz-AFK/3, Fy-AFK/3, Fy-A/2
  half/1 -> Fx-u/2, Fy-v/2, Fz-w/2
  V^2-u/1 -> Fx-u/1
  VelDiff-w/1 -> V-w/1, V^2-w/2
  w-V-Sum/1 -> VelDiff-w/1
  u-V-Sum/1 -> VelDiff-u/1
  Uz/1 -> VelDiff-w/2
  Ux/1 -> VelDiff-u/2
  Uy/1 -> VelDiff-v/2
  Add Vel/1 -> Uz/1, Uy/1, Ux/1
  "dot{U}z"/1 -> AccelDiff-w/2
  x-A-Sum/1 -> AccelDiff-x/1, Fx-AFK/1
  "dot{U}x"/1 -> AccelDiff-x/2
  "dot{U}y"/1 -> AccelDiff-v/2
  ShiftCg/1 -> Zshift/1, MorisonElementIrregular/1(Disp)
  Disp-sl/1 -> ShiftCg/2
  r x 3x3/1 -> ShiftCg/1, "r_{cg} x F"/1
  Rotation3/1(rot[3,1-3]) -> 3x3/3
  Rotation1/1(rot[1,1-3]) -> 3x3/1
  Rotation2/1(rot[2,1-3]) -> 3x3/2
  rot2/1 -> Rotation1/2(rot2), Rotation2/2(rot2), Rotation3/2(rot2)
  rot1/1 -> Rotation1/1(rot1), Rotation2/1(rot1), Rotation3/1(rot1)
  rot3/1 -> Rotation1/3(rot3), Rotation2/3(rot3)
  Disp-sr/1 -> rot1/1, rot2/1, rot3/1
  Disp/1 -> Disp-sr/1, Disp-sl/1
  Vel-sl/1 -> Add Vel/1
  Add Accel/1 -> "dot{U}x"/1, "dot{U}y"/1, "dot{U}z"/1
  Accel-sl/1 -> Add Accel/3
  "dot{w} x r2"/1 -> Add Accel/2
  Accel-sr/1 -> "dot{w} x r2"/1
  Accel/1 -> Accel-sr/1, Accel-sl/1
  r/1 -> w x r/2, "dot{w} x r2"/2, r x 3x3/1
  "Vel-sr "/1 -> w x r/1, w x w x r/1
  w x w x r/1 -> Add Accel/1
  w x r/1 -> w x w x r/2, Add Vel/2
  Vel/1 -> "Vel-sr "/1, Vel-sl/1

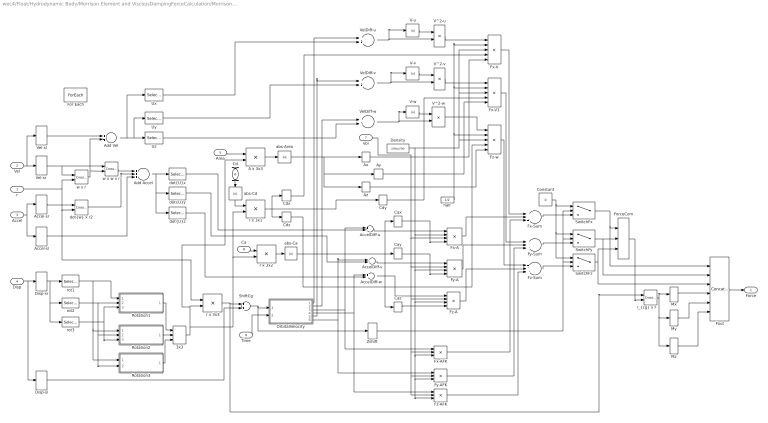
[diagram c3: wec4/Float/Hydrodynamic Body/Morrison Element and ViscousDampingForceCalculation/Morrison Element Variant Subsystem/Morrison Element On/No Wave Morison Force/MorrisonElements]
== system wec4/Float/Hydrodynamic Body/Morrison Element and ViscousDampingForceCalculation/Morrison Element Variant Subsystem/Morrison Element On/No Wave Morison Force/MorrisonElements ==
  r : Inport  Partition=on  PartitionDimension=1  PartitionWidth=1
  Vel : Inport  Port=2
  Accel : Inport  Port=3
  Disp : Inport  Port=4
  Area : Inport  Port=5  Partition=on  PartitionDimension=1  PartitionWidth=1
  Cd : Inport  Port=6  Partition=on  PartitionDimension=1  PartitionWidth=1
  Vol : Inport  Port=7  Partition=on  PartitionDimension=1  PartitionWidth=1
  Ca : Inport  Port=8  Partition=on  PartitionDimension=1  PartitionWidth=1
  Time : Inport  Port=9
  3x3 : Concatenate  NumInputs=3  Mode=Multidimensional array
  A x 3x3 : Product  Multiplication=Matrix(*)
  Accel-sl : Selector  InputPortWidth=6  IndexOptions=Index vector (dialog)  Indices=[1 2 3]  OutputSizes=1
  Accel-sr : Selector  InputPortWidth=6  IndexOptions=Index vector (dialog)  Indices=[4 5 6]  OutputSizes=1
  AccelDiff-u : Sum  Inputs=+-
  AccelDiff-v : Sum  Inputs=+-
  AccelDiff-w : Sum  Inputs=+-
  Add Accel : Sum  Inputs=+++
  Add Vel : Sum
  Ax : Selector  InputPortWidth=3  IndexOptions=Index vector (dialog)  Indices=[1]  OutputSizes=1
  Ay : Selector  InputPortWidth=3  IndexOptions=Index vector (dialog)  Indices=[2]  OutputSizes=1
  Az : Selector  InputPortWidth=3  IndexOptions=Index vector (dialog)  Indices=[3]  OutputSizes=1
  Cax : Selector  InputPortWidth=3  IndexOptions=Index vector (dialog)  Indices=[1]  OutputSizes=1
  Cay : Selector  InputPortWidth=3  IndexOptions=Index vector (dialog)  Indices=[2]  OutputSizes=1
  Caz : Selector  InputPortWidth=3  IndexOptions=Index vector (dialog)  Indices=[3]  OutputSizes=1
  Cdx : Selector  InputPortWidth=3  IndexOptions=Index vector (dialog)  Indices=[1]  OutputSizes=1
  Cdy : Selector  InputPortWidth=3  IndexOptions=Index vector (dialog)  Indices=[2]  OutputSizes=1
  Cdz : Selector  InputPortWidth=3  IndexOptions=Index vector (dialog)  Indices=[3]  OutputSizes=1
  Constant : Constant  Value=0
  Density : Constant  Value=simu.rho
  Disp-sl : Selector  InputPortWidth=6  IndexOptions=Index vector (dialog)  Indices=[1 2 3]  OutputSizes=1
  Disp-sr : Selector  InputPortWidth=6  IndexOptions=Index vector (dialog)  Indices=[4 5 6]  OutputSizes=1
  For Each : ForEach  DisableCoverage=on  IndexMode=One-based
  ForceCom : Concatenate  NumInputs=3  ConcatenateDimension=2
  Fout : Concatenate  NumInputs=6  Mode=Multidimensional array  ConcatenateDimension=2
  Fx-A : Product  Inputs=4
  Fx-AFK : Product  Inputs=3
  Fx-Sum : Sum  Inputs=+++
  Fx-V : Product  Inputs=5
  Fx-V1 : Product  Inputs=5
  Fy-A : Product  Inputs=4
  Fy-AFK : Product  Inputs=3
  Fy-Sum : Sum  Inputs=+++
  Fz-A : Product  Inputs=4
  Fz-AFK : Product  Inputs=3
  Fz-Sum : Sum  Inputs=+++
  Fz-w : Product  Inputs=5
  Mx : Selector  InputPortWidth=3  IndexOptions=Index vector (dialog)  Indices=[1]  OutputSizes=1
  My : Selector  InputPortWidth=3  IndexOptions=Index vector (dialog)  Indices=[2]  OutputSizes=1
  Mz : Selector  InputPortWidth=3  IndexOptions=Index vector (dialog)  Indices=[3]  OutputSizes=1
  OrbitalVelocity : Subsystem
  Rotation1 : Subsystem
  Rotation2 : Subsystem
  Rotation3 : Subsystem
  ShiftCg : Sum
  SwitchFx : Switch  Criteria=u2 > Threshold
  SwitchFy : Switch  Criteria=u2 > Threshold
  SwitchFz : Switch  Criteria=u2 > Threshold
  Ux : Selector  InputPortWidth=3  IndexOptions=Index vector (dialog)  Indices=[1]  OutputSizes=1
  Uy : Selector  InputPortWidth=3  IndexOptions=Index vector (dialog)  Indices=[2]  OutputSizes=1
  Uz : Selector  InputPortWidth=3  IndexOptions=Index vector (dialog)  Indices=[3]  OutputSizes=1
  V-u : Abs
  V-v : Abs
  V-w : Abs
  V^2-u : Product
  V^2-v : Product
  V^2-w : Product
  Vel-sl : Selector  InputPortWidth=6  IndexOptions=Index vector (dialog)  Indices=[1 2 3]  OutputSizes=1
  "Vel-sr " : Selector  InputPortWidth=6  IndexOptions=Index vector (dialog)  Indices=[4 5 6]  OutputSizes=1
  VelDiff-u : Sum  Inputs=+-
  VelDiff-v : Sum  Inputs=+-
  VelDiff-w : Sum  Inputs=+-
  Zshift : Selector  InputPortWidth=3  IndexOptions=Index vector (dialog)  Indices=[3]  OutputSizes=1
  abs-Area : Abs
  abs-Ca : Abs
  abs-Cd : Abs
  "dot{U}x" : Selector  InputPortWidth=3  IndexOptions=Index vector (dialog)  Indices=[1]  OutputSizes=1
  "dot{U}y" : Selector  InputPortWidth=3  IndexOptions=Index vector (dialog)  Indices=[2]  OutputSizes=1
  "dot{U}z" : Selector  InputPortWidth=3  IndexOptions=Index vector (dialog)  Indices=[3]  OutputSizes=1
  "dot{w} x r2" : vrlib/Utilities/Cross Product
  half : Constant  Value=1/2
  r x 3x1 : Product  Multiplication=Matrix(*)
  r x 3x2 : Product  Multiplication=Matrix(*)
  r x 3x3 : Product  Multiplication=Matrix(*)
  "r_{cg} x F" : vrlib/Utilities/Cross Product
  rot1 : Selector  InputPortWidth=3  IndexOptions=Index vector (dialog)  Indices=[1]  OutputSizes=1
  rot2 : Selector  InputPortWidth=3  IndexOptions=Index vector (dialog)  Indices=[2]  OutputSizes=1
  rot3 : Selector  InputPortWidth=3  IndexOptions=Index vector (dialog)  Indices=[3]  OutputSizes=1
  w x r : vrlib/Utilities/Cross Product
  w x w x r : vrlib/Utilities/Cross Product
  Force : Outport  PortDimensions=[1 6]  ConcatenationDimension=1
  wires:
  Time/1 -> OrbitalVelocity/2(Time)
  abs-Cd/1 -> r x 3x1/1
  abs-Ca/1 -> Caz/1, Cay/1, Cax/1
  V-w/1 -> V^2-w/1
  Constant/1 -> SwitchFx/1, SwitchFz/1, SwitchFy/1
  Fx-V1/1 -> Fy-Sum/1
  Fy-A/1 -> Fy-Sum/2
  Cay/1 -> Fy-A/4
  AccelDiff-v/1 -> Fy-A/1
  Fy-AFK/1 -> Fy-Sum/3
  Fy-Sum/1 -> SwitchFy/3
  SwitchFy/1 -> ForceCom/2, Fout/2
  Cdy/1 -> Fx-V1/4
  Ay/1 -> Fx-V1/5
  OrbitalVelocity/5(v-V) -> VelDiff-v/1
  VelDiff-v/1 -> V^2-v/2, V-v/1
  V-v/1 -> V^2-v/1
  V^2-v/1 -> Fx-V1/1
  OrbitalVelocity/6(v-A) -> Fy-AFK/1, AccelDiff-v/1
  r x 3x2/1 -> abs-Ca/1
  Ca/1 -> r x 3x2/1
  r x 3x1/1 -> Cdx/1, Cdz/1, Cdy/1
  Cd/1 -> abs-Cd/1
  Cax/1 -> Fx-A/4
  Caz/1 -> Fz-A/4
  Fout/1 -> Force/1
  ForceCom/1 -> "r_{cg} x F"/2
  abs-Area/1 -> Ax/1, Az/1, Ay/1
  A x 3x3/1 -> abs-Area/1
  Cdz/1 -> Fz-w/4
  Cdx/1 -> Fx-V/4
  Ax/1 -> Fx-V/5
  Area/1 -> A x 3x3/1
  Az/1 -> Fz-w/5
  Fz-Sum/1 -> SwitchFz/3
  Fx-Sum/1 -> SwitchFx/3
  SwitchFx/1 -> ForceCom/1, Fout/1
  SwitchFz/1 -> Fout/3, ForceCom/3
  Zshift/1 -> SwitchFz/2, SwitchFx/2, SwitchFy/2
  VelDiff-u/1 -> V^2-u/2, V-u/1
  V-u/1 -> V^2-u/1
  3x3/1 -> r x 3x1/2, r x 3x2/2, r x 3x3/2, A x 3x3/2
  Mz/1 -> Fout/6
  My/1 -> Fout/5
  Mx/1 -> Fout/4
  "r_{cg} x F"/1 -> Mx/1, My/1, Mz/1
  Fz-AFK/1 -> Fz-Sum/3
  Fz-A/1 -> Fz-Sum/2
  Fz-w/1 -> Fz-Sum/1
  Fx-AFK/1 -> Fx-Sum/3
  Fx-A/1 -> Fx-Sum/2
  Fx-V/1 -> Fx-Sum/1
  OrbitalVelocity/4(w-A) -> AccelDiff-w/1, Fz-AFK/1
  AccelDiff-w/1 -> Fz-A/1
  Vol/1 -> Fx-A/3, Fz-A/2, Fx-AFK/2, Fz-AFK/2, Fy-AFK/2, Fy-A/2
  AccelDiff-u/1 -> Fx-A/1
  V^2-w/1 -> Fz-w/1
  Density/1 -> Fx-V/3, Fx-V1/3, Fz-w/3, Fx-A/2, Fz-A/3, Fx-AFK/3, Fz-AFK/3, Fy-AFK/3, Fy-A/3
  half/1 -> Fx-V/2, Fx-V1/2, Fz-w/2
  V^2-u/1 -> Fx-V/1
  VelDiff-w/1 -> V^2-w/2, V-w/1
  OrbitalVelocity/2(w-V) -> VelDiff-w/1
  OrbitalVelocity/1(u-V) -> VelDiff-u/1
  Uz/1 -> VelDiff-w/2
  Ux/1 -> VelDiff-u/2
  Uy/1 -> VelDiff-v/2
  Add Vel/1 -> Ux/1, Uz/1, Uy/1
  "dot{U}z"/1 -> AccelDiff-w/2
  OrbitalVelocity/3(u-A) -> Fx-AFK/1, AccelDiff-u/1
  "dot{U}x"/1 -> AccelDiff-u/2
  "dot{U}y"/1 -> AccelDiff-v/2
  ShiftCg/1 -> OrbitalVelocity/1(Disp), Zshift/1
  Disp-sl/1 -> ShiftCg/2
  r x 3x3/1 -> ShiftCg/1, "r_{cg} x F"/1
  Rotation3/1(rot[3,1-3]) -> 3x3/3
  Rotation1/1(rot[1,1-3]) -> 3x3/1
  Rotation2/1(rot[2,1-3]) -> 3x3/2
  rot2/1 -> Rotation1/2(rot2), Rotation2/2(rot2), Rotation3/2(rot2)
  rot1/1 -> Rotation1/1(rot1), Rotation2/1(rot1), Rotation3/1(rot1)
  rot3/1 -> Rotation1/3(rot3), Rotation2/3(rot3)
  Disp-sr/1 -> rot1/1, rot2/1, rot3/1
  Disp/1 -> Disp-sr/1, Disp-sl/1
  Vel-sl/1 -> Add Vel/1
  Add Accel/1 -> "dot{U}x"/1, "dot{U}y"/1, "dot{U}z"/1
  Accel-sl/1 -> Add Accel/3
  "dot{w} x r2"/1 -> Add Accel/2
  Accel-sr/1 -> "dot{w} x r2"/1
  Accel/1 -> Accel-sr/1, Accel-sl/1
  r/1 -> w x r/2, "dot{w} x r2"/2, r x 3x3/1
  "Vel-sr "/1 -> w x r/1, w x w x r/1
  w x w x r/1 -> Add Accel/1
  w x r/1 -> w x w x r/2, Add Vel/2
  Vel/1 -> "Vel-sr "/1, Vel-sl/1
